VERSION 5.8 ;
BUSBITCHARS "[]" ;
DIVIDERCHAR "/" ;
UNITS
    DATABASE MICRONS 1000 ;
END UNITS

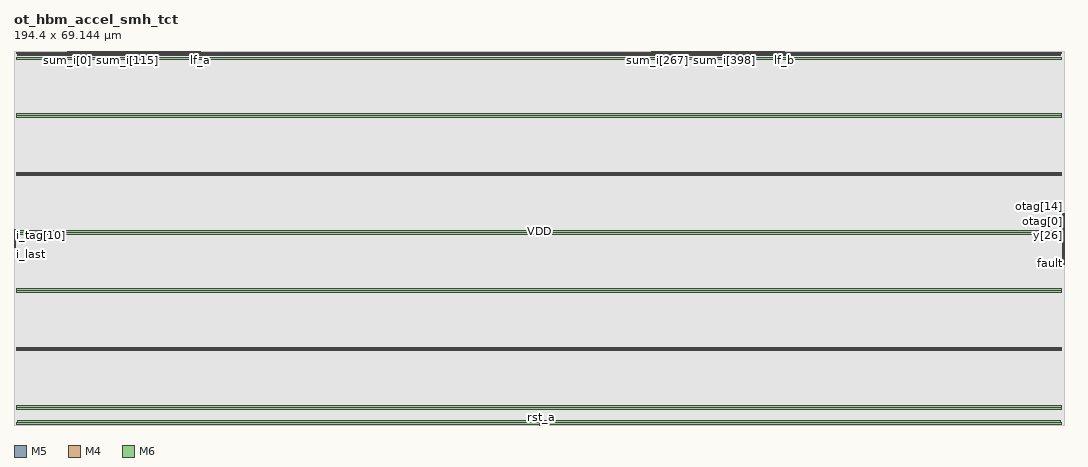
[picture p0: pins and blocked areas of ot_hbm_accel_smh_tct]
MACRO ot_hbm_accel_smh_tct
  FOREIGN ot_hbm_accel_smh_tct 0 0 ;
  CLASS BLOCK ;
  SIZE 194.4 BY 69.144 ;
  PIN clk
    DIRECTION INPUT ;
    USE SIGNAL ;
    PORT
      LAYER M5 ;
        RECT  97.2 0 97.224 0.192 ;
    END
  END clk
  PIN fault
    DIRECTION OUTPUT ;
    USE SIGNAL ;
    PORT
      LAYER M4 ;
        RECT  194.208 29.952 194.4 29.976 ;
    END
  END fault
  PIN i_last
    DIRECTION INPUT ;
    USE SIGNAL ;
    PORT
      LAYER M4 ;
        RECT  0 33.024 0.192 33.048 ;
    END
  END i_last
  PIN i_tag[0]
    DIRECTION INPUT ;
    USE SIGNAL ;
    PORT
      LAYER M4 ;
        RECT  0 33.216 0.192 33.24 ;
    END
  END i_tag[0]
  PIN i_tag[10]
    DIRECTION INPUT ;
    USE SIGNAL ;
    PORT
      LAYER M4 ;
        RECT  0 35.136 0.192 35.16 ;
    END
  END i_tag[10]
  PIN i_tag[11]
    DIRECTION INPUT ;
    USE SIGNAL ;
    PORT
      LAYER M4 ;
        RECT  0 35.328 0.192 35.352 ;
    END
  END i_tag[11]
  PIN i_tag[12]
    DIRECTION INPUT ;
    USE SIGNAL ;
    PORT
      LAYER M4 ;
        RECT  0 35.52 0.192 35.544 ;
    END
  END i_tag[12]
  PIN i_tag[13]
    DIRECTION INPUT ;
    USE SIGNAL ;
    PORT
      LAYER M4 ;
        RECT  0 35.712 0.192 35.736 ;
    END
  END i_tag[13]
  PIN i_tag[14]
    DIRECTION INPUT ;
    USE SIGNAL ;
    PORT
      LAYER M4 ;
        RECT  0 35.904 0.192 35.928 ;
    END
  END i_tag[14]
  PIN i_tag[15]
    DIRECTION INPUT ;
    USE SIGNAL ;
    PORT
      LAYER M4 ;
        RECT  0 36.096 0.192 36.12 ;
    END
  END i_tag[15]
  PIN i_tag[1]
    DIRECTION INPUT ;
    USE SIGNAL ;
    PORT
      LAYER M4 ;
        RECT  0 33.408 0.192 33.432 ;
    END
  END i_tag[1]
  PIN i_tag[2]
    DIRECTION INPUT ;
    USE SIGNAL ;
    PORT
      LAYER M4 ;
        RECT  0 33.6 0.192 33.624 ;
    END
  END i_tag[2]
  PIN i_tag[3]
    DIRECTION INPUT ;
    USE SIGNAL ;
    PORT
      LAYER M4 ;
        RECT  0 33.792 0.192 33.816 ;
    END
  END i_tag[3]
  PIN i_tag[4]
    DIRECTION INPUT ;
    USE SIGNAL ;
    PORT
      LAYER M4 ;
        RECT  0 33.984 0.192 34.008 ;
    END
  END i_tag[4]
  PIN i_tag[5]
    DIRECTION INPUT ;
    USE SIGNAL ;
    PORT
      LAYER M4 ;
        RECT  0 34.176 0.192 34.2 ;
    END
  END i_tag[5]
  PIN i_tag[6]
    DIRECTION INPUT ;
    USE SIGNAL ;
    PORT
      LAYER M4 ;
        RECT  0 34.368 0.192 34.392 ;
    END
  END i_tag[6]
  PIN i_tag[7]
    DIRECTION INPUT ;
    USE SIGNAL ;
    PORT
      LAYER M4 ;
        RECT  0 34.56 0.192 34.584 ;
    END
  END i_tag[7]
  PIN i_tag[8]
    DIRECTION INPUT ;
    USE SIGNAL ;
    PORT
      LAYER M4 ;
        RECT  0 34.752 0.192 34.776 ;
    END
  END i_tag[8]
  PIN i_tag[9]
    DIRECTION INPUT ;
    USE SIGNAL ;
    PORT
      LAYER M4 ;
        RECT  0 34.944 0.192 34.968 ;
    END
  END i_tag[9]
  PIN i_v
    DIRECTION INPUT ;
    USE SIGNAL ;
    PORT
      LAYER M4 ;
        RECT  0 32.832 0.192 32.856 ;
    END
  END i_v
  PIN lf_a
    DIRECTION INPUT ;
    USE SIGNAL ;
    PORT
      LAYER M5 ;
        RECT  34.56 68.952 34.584 69.144 ;
    END
  END lf_a
  PIN lf_b
    DIRECTION INPUT ;
    USE SIGNAL ;
    PORT
      LAYER M5 ;
        RECT  142.56 68.952 142.584 69.144 ;
    END
  END lf_b
  PIN otag[0]
    DIRECTION OUTPUT ;
    USE SIGNAL ;
    PORT
      LAYER M4 ;
        RECT  194.208 36.288 194.4 36.312 ;
    END
  END otag[0]
  PIN otag[10]
    DIRECTION OUTPUT ;
    USE SIGNAL ;
    PORT
      LAYER M4 ;
        RECT  194.208 38.208 194.4 38.232 ;
    END
  END otag[10]
  PIN otag[11]
    DIRECTION OUTPUT ;
    USE SIGNAL ;
    PORT
      LAYER M4 ;
        RECT  194.208 38.4 194.4 38.424 ;
    END
  END otag[11]
  PIN otag[12]
    DIRECTION OUTPUT ;
    USE SIGNAL ;
    PORT
      LAYER M4 ;
        RECT  194.208 38.592 194.4 38.616 ;
    END
  END otag[12]
  PIN otag[13]
    DIRECTION OUTPUT ;
    USE SIGNAL ;
    PORT
      LAYER M4 ;
        RECT  194.208 38.784 194.4 38.808 ;
    END
  END otag[13]
  PIN otag[14]
    DIRECTION OUTPUT ;
    USE SIGNAL ;
    PORT
      LAYER M4 ;
        RECT  194.208 38.976 194.4 39 ;
    END
  END otag[14]
  PIN otag[15]
    DIRECTION OUTPUT ;
    USE SIGNAL ;
    PORT
      LAYER M4 ;
        RECT  194.208 39.168 194.4 39.192 ;
    END
  END otag[15]
  PIN otag[1]
    DIRECTION OUTPUT ;
    USE SIGNAL ;
    PORT
      LAYER M4 ;
        RECT  194.208 36.48 194.4 36.504 ;
    END
  END otag[1]
  PIN otag[2]
    DIRECTION OUTPUT ;
    USE SIGNAL ;
    PORT
      LAYER M4 ;
        RECT  194.208 36.672 194.4 36.696 ;
    END
  END otag[2]
  PIN otag[3]
    DIRECTION OUTPUT ;
    USE SIGNAL ;
    PORT
      LAYER M4 ;
        RECT  194.208 36.864 194.4 36.888 ;
    END
  END otag[3]
  PIN otag[4]
    DIRECTION OUTPUT ;
    USE SIGNAL ;
    PORT
      LAYER M4 ;
        RECT  194.208 37.056 194.4 37.08 ;
    END
  END otag[4]
  PIN otag[5]
    DIRECTION OUTPUT ;
    USE SIGNAL ;
    PORT
      LAYER M4 ;
        RECT  194.208 37.248 194.4 37.272 ;
    END
  END otag[5]
  PIN otag[6]
    DIRECTION OUTPUT ;
    USE SIGNAL ;
    PORT
      LAYER M4 ;
        RECT  194.208 37.44 194.4 37.464 ;
    END
  END otag[6]
  PIN otag[7]
    DIRECTION OUTPUT ;
    USE SIGNAL ;
    PORT
      LAYER M4 ;
        RECT  194.208 37.632 194.4 37.656 ;
    END
  END otag[7]
  PIN otag[8]
    DIRECTION OUTPUT ;
    USE SIGNAL ;
    PORT
      LAYER M4 ;
        RECT  194.208 37.824 194.4 37.848 ;
    END
  END otag[8]
  PIN otag[9]
    DIRECTION OUTPUT ;
    USE SIGNAL ;
    PORT
      LAYER M4 ;
        RECT  194.208 38.016 194.4 38.04 ;
    END
  END otag[9]
  PIN ov
    DIRECTION OUTPUT ;
    USE SIGNAL ;
    PORT
      LAYER M4 ;
        RECT  194.208 29.76 194.4 29.784 ;
    END
  END ov
  PIN rst_a
    DIRECTION INPUT ;
    USE SIGNAL ;
    PORT
      LAYER M5 ;
        RECT  97.68 0 97.704 0.192 ;
    END
  END rst_a
  PIN sum_i[0]
    DIRECTION INPUT ;
    USE SIGNAL ;
    PORT
      LAYER M5 ;
        RECT  9.984 68.952 10.008 69.144 ;
    END
  END sum_i[0]
  PIN sum_i[100]
    DIRECTION INPUT ;
    USE SIGNAL ;
    PORT
      LAYER M5 ;
        RECT  19.584 68.952 19.608 69.144 ;
    END
  END sum_i[100]
  PIN sum_i[101]
    DIRECTION INPUT ;
    USE SIGNAL ;
    PORT
      LAYER M5 ;
        RECT  19.68 68.952 19.704 69.144 ;
    END
  END sum_i[101]
  PIN sum_i[102]
    DIRECTION INPUT ;
    USE SIGNAL ;
    PORT
      LAYER M5 ;
        RECT  19.776 68.952 19.8 69.144 ;
    END
  END sum_i[102]
  PIN sum_i[103]
    DIRECTION INPUT ;
    USE SIGNAL ;
    PORT
      LAYER M5 ;
        RECT  19.872 68.952 19.896 69.144 ;
    END
  END sum_i[103]
  PIN sum_i[104]
    DIRECTION INPUT ;
    USE SIGNAL ;
    PORT
      LAYER M5 ;
        RECT  19.968 68.952 19.992 69.144 ;
    END
  END sum_i[104]
  PIN sum_i[105]
    DIRECTION INPUT ;
    USE SIGNAL ;
    PORT
      LAYER M5 ;
        RECT  20.064 68.952 20.088 69.144 ;
    END
  END sum_i[105]
  PIN sum_i[106]
    DIRECTION INPUT ;
    USE SIGNAL ;
    PORT
      LAYER M5 ;
        RECT  20.16 68.952 20.184 69.144 ;
    END
  END sum_i[106]
  PIN sum_i[107]
    DIRECTION INPUT ;
    USE SIGNAL ;
    PORT
      LAYER M5 ;
        RECT  20.256 68.952 20.28 69.144 ;
    END
  END sum_i[107]
  PIN sum_i[108]
    DIRECTION INPUT ;
    USE SIGNAL ;
    PORT
      LAYER M5 ;
        RECT  20.352 68.952 20.376 69.144 ;
    END
  END sum_i[108]
  PIN sum_i[109]
    DIRECTION INPUT ;
    USE SIGNAL ;
    PORT
      LAYER M5 ;
        RECT  20.448 68.952 20.472 69.144 ;
    END
  END sum_i[109]
  PIN sum_i[10]
    DIRECTION INPUT ;
    USE SIGNAL ;
    PORT
      LAYER M5 ;
        RECT  10.944 68.952 10.968 69.144 ;
    END
  END sum_i[10]
  PIN sum_i[110]
    DIRECTION INPUT ;
    USE SIGNAL ;
    PORT
      LAYER M5 ;
        RECT  20.544 68.952 20.568 69.144 ;
    END
  END sum_i[110]
  PIN sum_i[111]
    DIRECTION INPUT ;
    USE SIGNAL ;
    PORT
      LAYER M5 ;
        RECT  20.64 68.952 20.664 69.144 ;
    END
  END sum_i[111]
  PIN sum_i[112]
    DIRECTION INPUT ;
    USE SIGNAL ;
    PORT
      LAYER M5 ;
        RECT  20.736 68.952 20.76 69.144 ;
    END
  END sum_i[112]
  PIN sum_i[113]
    DIRECTION INPUT ;
    USE SIGNAL ;
    PORT
      LAYER M5 ;
        RECT  20.832 68.952 20.856 69.144 ;
    END
  END sum_i[113]
  PIN sum_i[114]
    DIRECTION INPUT ;
    USE SIGNAL ;
    PORT
      LAYER M5 ;
        RECT  20.928 68.952 20.952 69.144 ;
    END
  END sum_i[114]
  PIN sum_i[115]
    DIRECTION INPUT ;
    USE SIGNAL ;
    PORT
      LAYER M5 ;
        RECT  21.024 68.952 21.048 69.144 ;
    END
  END sum_i[115]
  PIN sum_i[116]
    DIRECTION INPUT ;
    USE SIGNAL ;
    PORT
      LAYER M5 ;
        RECT  21.12 68.952 21.144 69.144 ;
    END
  END sum_i[116]
  PIN sum_i[117]
    DIRECTION INPUT ;
    USE SIGNAL ;
    PORT
      LAYER M5 ;
        RECT  21.216 68.952 21.24 69.144 ;
    END
  END sum_i[117]
  PIN sum_i[118]
    DIRECTION INPUT ;
    USE SIGNAL ;
    PORT
      LAYER M5 ;
        RECT  21.312 68.952 21.336 69.144 ;
    END
  END sum_i[118]
  PIN sum_i[119]
    DIRECTION INPUT ;
    USE SIGNAL ;
    PORT
      LAYER M5 ;
        RECT  21.408 68.952 21.432 69.144 ;
    END
  END sum_i[119]
  PIN sum_i[11]
    DIRECTION INPUT ;
    USE SIGNAL ;
    PORT
      LAYER M5 ;
        RECT  11.04 68.952 11.064 69.144 ;
    END
  END sum_i[11]
  PIN sum_i[120]
    DIRECTION INPUT ;
    USE SIGNAL ;
    PORT
      LAYER M5 ;
        RECT  21.504 68.952 21.528 69.144 ;
    END
  END sum_i[120]
  PIN sum_i[121]
    DIRECTION INPUT ;
    USE SIGNAL ;
    PORT
      LAYER M5 ;
        RECT  21.6 68.952 21.624 69.144 ;
    END
  END sum_i[121]
  PIN sum_i[122]
    DIRECTION INPUT ;
    USE SIGNAL ;
    PORT
      LAYER M5 ;
        RECT  21.696 68.952 21.72 69.144 ;
    END
  END sum_i[122]
  PIN sum_i[123]
    DIRECTION INPUT ;
    USE SIGNAL ;
    PORT
      LAYER M5 ;
        RECT  21.792 68.952 21.816 69.144 ;
    END
  END sum_i[123]
  PIN sum_i[124]
    DIRECTION INPUT ;
    USE SIGNAL ;
    PORT
      LAYER M5 ;
        RECT  21.888 68.952 21.912 69.144 ;
    END
  END sum_i[124]
  PIN sum_i[125]
    DIRECTION INPUT ;
    USE SIGNAL ;
    PORT
      LAYER M5 ;
        RECT  21.984 68.952 22.008 69.144 ;
    END
  END sum_i[125]
  PIN sum_i[126]
    DIRECTION INPUT ;
    USE SIGNAL ;
    PORT
      LAYER M5 ;
        RECT  22.08 68.952 22.104 69.144 ;
    END
  END sum_i[126]
  PIN sum_i[127]
    DIRECTION INPUT ;
    USE SIGNAL ;
    PORT
      LAYER M5 ;
        RECT  22.176 68.952 22.2 69.144 ;
    END
  END sum_i[127]
  PIN sum_i[128]
    DIRECTION INPUT ;
    USE SIGNAL ;
    PORT
      LAYER M5 ;
        RECT  22.272 68.952 22.296 69.144 ;
    END
  END sum_i[128]
  PIN sum_i[129]
    DIRECTION INPUT ;
    USE SIGNAL ;
    PORT
      LAYER M5 ;
        RECT  22.368 68.952 22.392 69.144 ;
    END
  END sum_i[129]
  PIN sum_i[12]
    DIRECTION INPUT ;
    USE SIGNAL ;
    PORT
      LAYER M5 ;
        RECT  11.136 68.952 11.16 69.144 ;
    END
  END sum_i[12]
  PIN sum_i[130]
    DIRECTION INPUT ;
    USE SIGNAL ;
    PORT
      LAYER M5 ;
        RECT  22.464 68.952 22.488 69.144 ;
    END
  END sum_i[130]
  PIN sum_i[131]
    DIRECTION INPUT ;
    USE SIGNAL ;
    PORT
      LAYER M5 ;
        RECT  22.56 68.952 22.584 69.144 ;
    END
  END sum_i[131]
  PIN sum_i[132]
    DIRECTION INPUT ;
    USE SIGNAL ;
    PORT
      LAYER M5 ;
        RECT  22.656 68.952 22.68 69.144 ;
    END
  END sum_i[132]
  PIN sum_i[133]
    DIRECTION INPUT ;
    USE SIGNAL ;
    PORT
      LAYER M5 ;
        RECT  22.752 68.952 22.776 69.144 ;
    END
  END sum_i[133]
  PIN sum_i[134]
    DIRECTION INPUT ;
    USE SIGNAL ;
    PORT
      LAYER M5 ;
        RECT  22.848 68.952 22.872 69.144 ;
    END
  END sum_i[134]
  PIN sum_i[135]
    DIRECTION INPUT ;
    USE SIGNAL ;
    PORT
      LAYER M5 ;
        RECT  22.944 68.952 22.968 69.144 ;
    END
  END sum_i[135]
  PIN sum_i[136]
    DIRECTION INPUT ;
    USE SIGNAL ;
    PORT
      LAYER M5 ;
        RECT  23.04 68.952 23.064 69.144 ;
    END
  END sum_i[136]
  PIN sum_i[137]
    DIRECTION INPUT ;
    USE SIGNAL ;
    PORT
      LAYER M5 ;
        RECT  23.136 68.952 23.16 69.144 ;
    END
  END sum_i[137]
  PIN sum_i[138]
    DIRECTION INPUT ;
    USE SIGNAL ;
    PORT
      LAYER M5 ;
        RECT  23.232 68.952 23.256 69.144 ;
    END
  END sum_i[138]
  PIN sum_i[139]
    DIRECTION INPUT ;
    USE SIGNAL ;
    PORT
      LAYER M5 ;
        RECT  23.328 68.952 23.352 69.144 ;
    END
  END sum_i[139]
  PIN sum_i[13]
    DIRECTION INPUT ;
    USE SIGNAL ;
    PORT
      LAYER M5 ;
        RECT  11.232 68.952 11.256 69.144 ;
    END
  END sum_i[13]
  PIN sum_i[140]
    DIRECTION INPUT ;
    USE SIGNAL ;
    PORT
      LAYER M5 ;
        RECT  23.424 68.952 23.448 69.144 ;
    END
  END sum_i[140]
  PIN sum_i[141]
    DIRECTION INPUT ;
    USE SIGNAL ;
    PORT
      LAYER M5 ;
        RECT  23.52 68.952 23.544 69.144 ;
    END
  END sum_i[141]
  PIN sum_i[142]
    DIRECTION INPUT ;
    USE SIGNAL ;
    PORT
      LAYER M5 ;
        RECT  23.616 68.952 23.64 69.144 ;
    END
  END sum_i[142]
  PIN sum_i[143]
    DIRECTION INPUT ;
    USE SIGNAL ;
    PORT
      LAYER M5 ;
        RECT  23.712 68.952 23.736 69.144 ;
    END
  END sum_i[143]
  PIN sum_i[144]
    DIRECTION INPUT ;
    USE SIGNAL ;
    PORT
      LAYER M5 ;
        RECT  23.808 68.952 23.832 69.144 ;
    END
  END sum_i[144]
  PIN sum_i[145]
    DIRECTION INPUT ;
    USE SIGNAL ;
    PORT
      LAYER M5 ;
        RECT  23.904 68.952 23.928 69.144 ;
    END
  END sum_i[145]
  PIN sum_i[146]
    DIRECTION INPUT ;
    USE SIGNAL ;
    PORT
      LAYER M5 ;
        RECT  24 68.952 24.024 69.144 ;
    END
  END sum_i[146]
  PIN sum_i[147]
    DIRECTION INPUT ;
    USE SIGNAL ;
    PORT
      LAYER M5 ;
        RECT  24.096 68.952 24.12 69.144 ;
    END
  END sum_i[147]
  PIN sum_i[148]
    DIRECTION INPUT ;
    USE SIGNAL ;
    PORT
      LAYER M5 ;
        RECT  24.192 68.952 24.216 69.144 ;
    END
  END sum_i[148]
  PIN sum_i[149]
    DIRECTION INPUT ;
    USE SIGNAL ;
    PORT
      LAYER M5 ;
        RECT  24.288 68.952 24.312 69.144 ;
    END
  END sum_i[149]
  PIN sum_i[14]
    DIRECTION INPUT ;
    USE SIGNAL ;
    PORT
      LAYER M5 ;
        RECT  11.328 68.952 11.352 69.144 ;
    END
  END sum_i[14]
  PIN sum_i[150]
    DIRECTION INPUT ;
    USE SIGNAL ;
    PORT
      LAYER M5 ;
        RECT  24.384 68.952 24.408 69.144 ;
    END
  END sum_i[150]
  PIN sum_i[151]
    DIRECTION INPUT ;
    USE SIGNAL ;
    PORT
      LAYER M5 ;
        RECT  24.48 68.952 24.504 69.144 ;
    END
  END sum_i[151]
  PIN sum_i[152]
    DIRECTION INPUT ;
    USE SIGNAL ;
    PORT
      LAYER M5 ;
        RECT  24.576 68.952 24.6 69.144 ;
    END
  END sum_i[152]
  PIN sum_i[153]
    DIRECTION INPUT ;
    USE SIGNAL ;
    PORT
      LAYER M5 ;
        RECT  24.672 68.952 24.696 69.144 ;
    END
  END sum_i[153]
  PIN sum_i[154]
    DIRECTION INPUT ;
    USE SIGNAL ;
    PORT
      LAYER M5 ;
        RECT  24.768 68.952 24.792 69.144 ;
    END
  END sum_i[154]
  PIN sum_i[155]
    DIRECTION INPUT ;
    USE SIGNAL ;
    PORT
      LAYER M5 ;
        RECT  24.864 68.952 24.888 69.144 ;
    END
  END sum_i[155]
  PIN sum_i[156]
    DIRECTION INPUT ;
    USE SIGNAL ;
    PORT
      LAYER M5 ;
        RECT  24.96 68.952 24.984 69.144 ;
    END
  END sum_i[156]
  PIN sum_i[157]
    DIRECTION INPUT ;
    USE SIGNAL ;
    PORT
      LAYER M5 ;
        RECT  25.056 68.952 25.08 69.144 ;
    END
  END sum_i[157]
  PIN sum_i[158]
    DIRECTION INPUT ;
    USE SIGNAL ;
    PORT
      LAYER M5 ;
        RECT  25.152 68.952 25.176 69.144 ;
    END
  END sum_i[158]
  PIN sum_i[159]
    DIRECTION INPUT ;
    USE SIGNAL ;
    PORT
      LAYER M5 ;
        RECT  25.248 68.952 25.272 69.144 ;
    END
  END sum_i[159]
  PIN sum_i[15]
    DIRECTION INPUT ;
    USE SIGNAL ;
    PORT
      LAYER M5 ;
        RECT  11.424 68.952 11.448 69.144 ;
    END
  END sum_i[15]
  PIN sum_i[160]
    DIRECTION INPUT ;
    USE SIGNAL ;
    PORT
      LAYER M5 ;
        RECT  25.344 68.952 25.368 69.144 ;
    END
  END sum_i[160]
  PIN sum_i[161]
    DIRECTION INPUT ;
    USE SIGNAL ;
    PORT
      LAYER M5 ;
        RECT  25.44 68.952 25.464 69.144 ;
    END
  END sum_i[161]
  PIN sum_i[162]
    DIRECTION INPUT ;
    USE SIGNAL ;
    PORT
      LAYER M5 ;
        RECT  25.536 68.952 25.56 69.144 ;
    END
  END sum_i[162]
  PIN sum_i[163]
    DIRECTION INPUT ;
    USE SIGNAL ;
    PORT
      LAYER M5 ;
        RECT  25.632 68.952 25.656 69.144 ;
    END
  END sum_i[163]
  PIN sum_i[164]
    DIRECTION INPUT ;
    USE SIGNAL ;
    PORT
      LAYER M5 ;
        RECT  25.728 68.952 25.752 69.144 ;
    END
  END sum_i[164]
  PIN sum_i[165]
    DIRECTION INPUT ;
    USE SIGNAL ;
    PORT
      LAYER M5 ;
        RECT  25.824 68.952 25.848 69.144 ;
    END
  END sum_i[165]
  PIN sum_i[166]
    DIRECTION INPUT ;
    USE SIGNAL ;
    PORT
      LAYER M5 ;
        RECT  25.92 68.952 25.944 69.144 ;
    END
  END sum_i[166]
  PIN sum_i[167]
    DIRECTION INPUT ;
    USE SIGNAL ;
    PORT
      LAYER M5 ;
        RECT  26.016 68.952 26.04 69.144 ;
    END
  END sum_i[167]
  PIN sum_i[168]
    DIRECTION INPUT ;
    USE SIGNAL ;
    PORT
      LAYER M5 ;
        RECT  26.112 68.952 26.136 69.144 ;
    END
  END sum_i[168]
  PIN sum_i[169]
    DIRECTION INPUT ;
    USE SIGNAL ;
    PORT
      LAYER M5 ;
        RECT  26.208 68.952 26.232 69.144 ;
    END
  END sum_i[169]
  PIN sum_i[16]
    DIRECTION INPUT ;
    USE SIGNAL ;
    PORT
      LAYER M5 ;
        RECT  11.52 68.952 11.544 69.144 ;
    END
  END sum_i[16]
  PIN sum_i[170]
    DIRECTION INPUT ;
    USE SIGNAL ;
    PORT
      LAYER M5 ;
        RECT  26.304 68.952 26.328 69.144 ;
    END
  END sum_i[170]
  PIN sum_i[171]
    DIRECTION INPUT ;
    USE SIGNAL ;
    PORT
      LAYER M5 ;
        RECT  26.4 68.952 26.424 69.144 ;
    END
  END sum_i[171]
  PIN sum_i[172]
    DIRECTION INPUT ;
    USE SIGNAL ;
    PORT
      LAYER M5 ;
        RECT  26.496 68.952 26.52 69.144 ;
    END
  END sum_i[172]
  PIN sum_i[173]
    DIRECTION INPUT ;
    USE SIGNAL ;
    PORT
      LAYER M5 ;
        RECT  26.592 68.952 26.616 69.144 ;
    END
  END sum_i[173]
  PIN sum_i[174]
    DIRECTION INPUT ;
    USE SIGNAL ;
    PORT
      LAYER M5 ;
        RECT  26.688 68.952 26.712 69.144 ;
    END
  END sum_i[174]
  PIN sum_i[175]
    DIRECTION INPUT ;
    USE SIGNAL ;
    PORT
      LAYER M5 ;
        RECT  26.784 68.952 26.808 69.144 ;
    END
  END sum_i[175]
  PIN sum_i[176]
    DIRECTION INPUT ;
    USE SIGNAL ;
    PORT
      LAYER M5 ;
        RECT  26.88 68.952 26.904 69.144 ;
    END
  END sum_i[176]
  PIN sum_i[177]
    DIRECTION INPUT ;
    USE SIGNAL ;
    PORT
      LAYER M5 ;
        RECT  26.976 68.952 27 69.144 ;
    END
  END sum_i[177]
  PIN sum_i[178]
    DIRECTION INPUT ;
    USE SIGNAL ;
    PORT
      LAYER M5 ;
        RECT  27.072 68.952 27.096 69.144 ;
    END
  END sum_i[178]
  PIN sum_i[179]
    DIRECTION INPUT ;
    USE SIGNAL ;
    PORT
      LAYER M5 ;
        RECT  27.168 68.952 27.192 69.144 ;
    END
  END sum_i[179]
  PIN sum_i[17]
    DIRECTION INPUT ;
    USE SIGNAL ;
    PORT
      LAYER M5 ;
        RECT  11.616 68.952 11.64 69.144 ;
    END
  END sum_i[17]
  PIN sum_i[180]
    DIRECTION INPUT ;
    USE SIGNAL ;
    PORT
      LAYER M5 ;
        RECT  27.264 68.952 27.288 69.144 ;
    END
  END sum_i[180]
  PIN sum_i[181]
    DIRECTION INPUT ;
    USE SIGNAL ;
    PORT
      LAYER M5 ;
        RECT  27.36 68.952 27.384 69.144 ;
    END
  END sum_i[181]
  PIN sum_i[182]
    DIRECTION INPUT ;
    USE SIGNAL ;
    PORT
      LAYER M5 ;
        RECT  27.456 68.952 27.48 69.144 ;
    END
  END sum_i[182]
  PIN sum_i[183]
    DIRECTION INPUT ;
    USE SIGNAL ;
    PORT
      LAYER M5 ;
        RECT  27.552 68.952 27.576 69.144 ;
    END
  END sum_i[183]
  PIN sum_i[184]
    DIRECTION INPUT ;
    USE SIGNAL ;
    PORT
      LAYER M5 ;
        RECT  27.648 68.952 27.672 69.144 ;
    END
  END sum_i[184]
  PIN sum_i[185]
    DIRECTION INPUT ;
    USE SIGNAL ;
    PORT
      LAYER M5 ;
        RECT  27.744 68.952 27.768 69.144 ;
    END
  END sum_i[185]
  PIN sum_i[186]
    DIRECTION INPUT ;
    USE SIGNAL ;
    PORT
      LAYER M5 ;
        RECT  27.84 68.952 27.864 69.144 ;
    END
  END sum_i[186]
  PIN sum_i[187]
    DIRECTION INPUT ;
    USE SIGNAL ;
    PORT
      LAYER M5 ;
        RECT  27.936 68.952 27.96 69.144 ;
    END
  END sum_i[187]
  PIN sum_i[188]
    DIRECTION INPUT ;
    USE SIGNAL ;
    PORT
      LAYER M5 ;
        RECT  28.032 68.952 28.056 69.144 ;
    END
  END sum_i[188]
  PIN sum_i[189]
    DIRECTION INPUT ;
    USE SIGNAL ;
    PORT
      LAYER M5 ;
        RECT  28.128 68.952 28.152 69.144 ;
    END
  END sum_i[189]
  PIN sum_i[18]
    DIRECTION INPUT ;
    USE SIGNAL ;
    PORT
      LAYER M5 ;
        RECT  11.712 68.952 11.736 69.144 ;
    END
  END sum_i[18]
  PIN sum_i[190]
    DIRECTION INPUT ;
    USE SIGNAL ;
    PORT
      LAYER M5 ;
        RECT  28.224 68.952 28.248 69.144 ;
    END
  END sum_i[190]
  PIN sum_i[191]
    DIRECTION INPUT ;
    USE SIGNAL ;
    PORT
      LAYER M5 ;
        RECT  28.32 68.952 28.344 69.144 ;
    END
  END sum_i[191]
  PIN sum_i[192]
    DIRECTION INPUT ;
    USE SIGNAL ;
    PORT
      LAYER M5 ;
        RECT  28.416 68.952 28.44 69.144 ;
    END
  END sum_i[192]
  PIN sum_i[193]
    DIRECTION INPUT ;
    USE SIGNAL ;
    PORT
      LAYER M5 ;
        RECT  28.512 68.952 28.536 69.144 ;
    END
  END sum_i[193]
  PIN sum_i[194]
    DIRECTION INPUT ;
    USE SIGNAL ;
    PORT
      LAYER M5 ;
        RECT  28.608 68.952 28.632 69.144 ;
    END
  END sum_i[194]
  PIN sum_i[195]
    DIRECTION INPUT ;
    USE SIGNAL ;
    PORT
      LAYER M5 ;
        RECT  28.704 68.952 28.728 69.144 ;
    END
  END sum_i[195]
  PIN sum_i[196]
    DIRECTION INPUT ;
    USE SIGNAL ;
    PORT
      LAYER M5 ;
        RECT  28.8 68.952 28.824 69.144 ;
    END
  END sum_i[196]
  PIN sum_i[197]
    DIRECTION INPUT ;
    USE SIGNAL ;
    PORT
      LAYER M5 ;
        RECT  28.896 68.952 28.92 69.144 ;
    END
  END sum_i[197]
  PIN sum_i[198]
    DIRECTION INPUT ;
    USE SIGNAL ;
    PORT
      LAYER M5 ;
        RECT  28.992 68.952 29.016 69.144 ;
    END
  END sum_i[198]
  PIN sum_i[199]
    DIRECTION INPUT ;
    USE SIGNAL ;
    PORT
      LAYER M5 ;
        RECT  29.088 68.952 29.112 69.144 ;
    END
  END sum_i[199]
  PIN sum_i[19]
    DIRECTION INPUT ;
    USE SIGNAL ;
    PORT
      LAYER M5 ;
        RECT  11.808 68.952 11.832 69.144 ;
    END
  END sum_i[19]
  PIN sum_i[1]
    DIRECTION INPUT ;
    USE SIGNAL ;
    PORT
      LAYER M5 ;
        RECT  10.08 68.952 10.104 69.144 ;
    END
  END sum_i[1]
  PIN sum_i[200]
    DIRECTION INPUT ;
    USE SIGNAL ;
    PORT
      LAYER M5 ;
        RECT  29.184 68.952 29.208 69.144 ;
    END
  END sum_i[200]
  PIN sum_i[201]
    DIRECTION INPUT ;
    USE SIGNAL ;
    PORT
      LAYER M5 ;
        RECT  29.28 68.952 29.304 69.144 ;
    END
  END sum_i[201]
  PIN sum_i[202]
    DIRECTION INPUT ;
    USE SIGNAL ;
    PORT
      LAYER M5 ;
        RECT  29.376 68.952 29.4 69.144 ;
    END
  END sum_i[202]
  PIN sum_i[203]
    DIRECTION INPUT ;
    USE SIGNAL ;
    PORT
      LAYER M5 ;
        RECT  29.472 68.952 29.496 69.144 ;
    END
  END sum_i[203]
  PIN sum_i[204]
    DIRECTION INPUT ;
    USE SIGNAL ;
    PORT
      LAYER M5 ;
        RECT  29.568 68.952 29.592 69.144 ;
    END
  END sum_i[204]
  PIN sum_i[205]
    DIRECTION INPUT ;
    USE SIGNAL ;
    PORT
      LAYER M5 ;
        RECT  29.664 68.952 29.688 69.144 ;
    END
  END sum_i[205]
  PIN sum_i[206]
    DIRECTION INPUT ;
    USE SIGNAL ;
    PORT
      LAYER M5 ;
        RECT  29.76 68.952 29.784 69.144 ;
    END
  END sum_i[206]
  PIN sum_i[207]
    DIRECTION INPUT ;
    USE SIGNAL ;
    PORT
      LAYER M5 ;
        RECT  29.856 68.952 29.88 69.144 ;
    END
  END sum_i[207]
  PIN sum_i[208]
    DIRECTION INPUT ;
    USE SIGNAL ;
    PORT
      LAYER M5 ;
        RECT  29.952 68.952 29.976 69.144 ;
    END
  END sum_i[208]
  PIN sum_i[209]
    DIRECTION INPUT ;
    USE SIGNAL ;
    PORT
      LAYER M5 ;
        RECT  30.048 68.952 30.072 69.144 ;
    END
  END sum_i[209]
  PIN sum_i[20]
    DIRECTION INPUT ;
    USE SIGNAL ;
    PORT
      LAYER M5 ;
        RECT  11.904 68.952 11.928 69.144 ;
    END
  END sum_i[20]
  PIN sum_i[210]
    DIRECTION INPUT ;
    USE SIGNAL ;
    PORT
      LAYER M5 ;
        RECT  30.144 68.952 30.168 69.144 ;
    END
  END sum_i[210]
  PIN sum_i[211]
    DIRECTION INPUT ;
    USE SIGNAL ;
    PORT
      LAYER M5 ;
        RECT  30.24 68.952 30.264 69.144 ;
    END
  END sum_i[211]
  PIN sum_i[212]
    DIRECTION INPUT ;
    USE SIGNAL ;
    PORT
      LAYER M5 ;
        RECT  30.336 68.952 30.36 69.144 ;
    END
  END sum_i[212]
  PIN sum_i[213]
    DIRECTION INPUT ;
    USE SIGNAL ;
    PORT
      LAYER M5 ;
        RECT  30.432 68.952 30.456 69.144 ;
    END
  END sum_i[213]
  PIN sum_i[214]
    DIRECTION INPUT ;
    USE SIGNAL ;
    PORT
      LAYER M5 ;
        RECT  30.528 68.952 30.552 69.144 ;
    END
  END sum_i[214]
  PIN sum_i[215]
    DIRECTION INPUT ;
    USE SIGNAL ;
    PORT
      LAYER M5 ;
        RECT  30.624 68.952 30.648 69.144 ;
    END
  END sum_i[215]
  PIN sum_i[216]
    DIRECTION INPUT ;
    USE SIGNAL ;
    PORT
      LAYER M5 ;
        RECT  30.72 68.952 30.744 69.144 ;
    END
  END sum_i[216]
  PIN sum_i[217]
    DIRECTION INPUT ;
    USE SIGNAL ;
    PORT
      LAYER M5 ;
        RECT  30.816 68.952 30.84 69.144 ;
    END
  END sum_i[217]
  PIN sum_i[218]
    DIRECTION INPUT ;
    USE SIGNAL ;
    PORT
      LAYER M5 ;
        RECT  30.912 68.952 30.936 69.144 ;
    END
  END sum_i[218]
  PIN sum_i[219]
    DIRECTION INPUT ;
    USE SIGNAL ;
    PORT
      LAYER M5 ;
        RECT  31.008 68.952 31.032 69.144 ;
    END
  END sum_i[219]
  PIN sum_i[21]
    DIRECTION INPUT ;
    USE SIGNAL ;
    PORT
      LAYER M5 ;
        RECT  12 68.952 12.024 69.144 ;
    END
  END sum_i[21]
  PIN sum_i[220]
    DIRECTION INPUT ;
    USE SIGNAL ;
    PORT
      LAYER M5 ;
        RECT  31.104 68.952 31.128 69.144 ;
    END
  END sum_i[220]
  PIN sum_i[221]
    DIRECTION INPUT ;
    USE SIGNAL ;
    PORT
      LAYER M5 ;
        RECT  31.2 68.952 31.224 69.144 ;
    END
  END sum_i[221]
  PIN sum_i[222]
    DIRECTION INPUT ;
    USE SIGNAL ;
    PORT
      LAYER M5 ;
        RECT  31.296 68.952 31.32 69.144 ;
    END
  END sum_i[222]
  PIN sum_i[223]
    DIRECTION INPUT ;
    USE SIGNAL ;
    PORT
      LAYER M5 ;
        RECT  31.392 68.952 31.416 69.144 ;
    END
  END sum_i[223]
  PIN sum_i[224]
    DIRECTION INPUT ;
    USE SIGNAL ;
    PORT
      LAYER M5 ;
        RECT  31.488 68.952 31.512 69.144 ;
    END
  END sum_i[224]
  PIN sum_i[225]
    DIRECTION INPUT ;
    USE SIGNAL ;
    PORT
      LAYER M5 ;
        RECT  31.584 68.952 31.608 69.144 ;
    END
  END sum_i[225]
  PIN sum_i[226]
    DIRECTION INPUT ;
    USE SIGNAL ;
    PORT
      LAYER M5 ;
        RECT  31.68 68.952 31.704 69.144 ;
    END
  END sum_i[226]
  PIN sum_i[227]
    DIRECTION INPUT ;
    USE SIGNAL ;
    PORT
      LAYER M5 ;
        RECT  31.776 68.952 31.8 69.144 ;
    END
  END sum_i[227]
  PIN sum_i[228]
    DIRECTION INPUT ;
    USE SIGNAL ;
    PORT
      LAYER M5 ;
        RECT  31.872 68.952 31.896 69.144 ;
    END
  END sum_i[228]
  PIN sum_i[229]
    DIRECTION INPUT ;
    USE SIGNAL ;
    PORT
      LAYER M5 ;
        RECT  31.968 68.952 31.992 69.144 ;
    END
  END sum_i[229]
  PIN sum_i[22]
    DIRECTION INPUT ;
    USE SIGNAL ;
    PORT
      LAYER M5 ;
        RECT  12.096 68.952 12.12 69.144 ;
    END
  END sum_i[22]
  PIN sum_i[230]
    DIRECTION INPUT ;
    USE SIGNAL ;
    PORT
      LAYER M5 ;
        RECT  32.064 68.952 32.088 69.144 ;
    END
  END sum_i[230]
  PIN sum_i[231]
    DIRECTION INPUT ;
    USE SIGNAL ;
    PORT
      LAYER M5 ;
        RECT  32.16 68.952 32.184 69.144 ;
    END
  END sum_i[231]
  PIN sum_i[232]
    DIRECTION INPUT ;
    USE SIGNAL ;
    PORT
      LAYER M5 ;
        RECT  32.256 68.952 32.28 69.144 ;
    END
  END sum_i[232]
  PIN sum_i[233]
    DIRECTION INPUT ;
    USE SIGNAL ;
    PORT
      LAYER M5 ;
        RECT  32.352 68.952 32.376 69.144 ;
    END
  END sum_i[233]
  PIN sum_i[234]
    DIRECTION INPUT ;
    USE SIGNAL ;
    PORT
      LAYER M5 ;
        RECT  32.448 68.952 32.472 69.144 ;
    END
  END sum_i[234]
  PIN sum_i[235]
    DIRECTION INPUT ;
    USE SIGNAL ;
    PORT
      LAYER M5 ;
        RECT  32.544 68.952 32.568 69.144 ;
    END
  END sum_i[235]
  PIN sum_i[236]
    DIRECTION INPUT ;
    USE SIGNAL ;
    PORT
      LAYER M5 ;
        RECT  32.64 68.952 32.664 69.144 ;
    END
  END sum_i[236]
  PIN sum_i[237]
    DIRECTION INPUT ;
    USE SIGNAL ;
    PORT
      LAYER M5 ;
        RECT  32.736 68.952 32.76 69.144 ;
    END
  END sum_i[237]
  PIN sum_i[238]
    DIRECTION INPUT ;
    USE SIGNAL ;
    PORT
      LAYER M5 ;
        RECT  32.832 68.952 32.856 69.144 ;
    END
  END sum_i[238]
  PIN sum_i[239]
    DIRECTION INPUT ;
    USE SIGNAL ;
    PORT
      LAYER M5 ;
        RECT  32.928 68.952 32.952 69.144 ;
    END
  END sum_i[239]
  PIN sum_i[23]
    DIRECTION INPUT ;
    USE SIGNAL ;
    PORT
      LAYER M5 ;
        RECT  12.192 68.952 12.216 69.144 ;
    END
  END sum_i[23]
  PIN sum_i[240]
    DIRECTION INPUT ;
    USE SIGNAL ;
    PORT
      LAYER M5 ;
        RECT  33.024 68.952 33.048 69.144 ;
    END
  END sum_i[240]
  PIN sum_i[241]
    DIRECTION INPUT ;
    USE SIGNAL ;
    PORT
      LAYER M5 ;
        RECT  33.12 68.952 33.144 69.144 ;
    END
  END sum_i[241]
  PIN sum_i[242]
    DIRECTION INPUT ;
    USE SIGNAL ;
    PORT
      LAYER M5 ;
        RECT  33.216 68.952 33.24 69.144 ;
    END
  END sum_i[242]
  PIN sum_i[243]
    DIRECTION INPUT ;
    USE SIGNAL ;
    PORT
      LAYER M5 ;
        RECT  33.312 68.952 33.336 69.144 ;
    END
  END sum_i[243]
  PIN sum_i[244]
    DIRECTION INPUT ;
    USE SIGNAL ;
    PORT
      LAYER M5 ;
        RECT  33.408 68.952 33.432 69.144 ;
    END
  END sum_i[244]
  PIN sum_i[245]
    DIRECTION INPUT ;
    USE SIGNAL ;
    PORT
      LAYER M5 ;
        RECT  33.504 68.952 33.528 69.144 ;
    END
  END sum_i[245]
  PIN sum_i[246]
    DIRECTION INPUT ;
    USE SIGNAL ;
    PORT
      LAYER M5 ;
        RECT  33.6 68.952 33.624 69.144 ;
    END
  END sum_i[246]
  PIN sum_i[247]
    DIRECTION INPUT ;
    USE SIGNAL ;
    PORT
      LAYER M5 ;
        RECT  33.696 68.952 33.72 69.144 ;
    END
  END sum_i[247]
  PIN sum_i[248]
    DIRECTION INPUT ;
    USE SIGNAL ;
    PORT
      LAYER M5 ;
        RECT  33.792 68.952 33.816 69.144 ;
    END
  END sum_i[248]
  PIN sum_i[249]
    DIRECTION INPUT ;
    USE SIGNAL ;
    PORT
      LAYER M5 ;
        RECT  33.888 68.952 33.912 69.144 ;
    END
  END sum_i[249]
  PIN sum_i[24]
    DIRECTION INPUT ;
    USE SIGNAL ;
    PORT
      LAYER M5 ;
        RECT  12.288 68.952 12.312 69.144 ;
    END
  END sum_i[24]
  PIN sum_i[250]
    DIRECTION INPUT ;
    USE SIGNAL ;
    PORT
      LAYER M5 ;
        RECT  33.984 68.952 34.008 69.144 ;
    END
  END sum_i[250]
  PIN sum_i[251]
    DIRECTION INPUT ;
    USE SIGNAL ;
    PORT
      LAYER M5 ;
        RECT  34.08 68.952 34.104 69.144 ;
    END
  END sum_i[251]
  PIN sum_i[252]
    DIRECTION INPUT ;
    USE SIGNAL ;
    PORT
      LAYER M5 ;
        RECT  34.176 68.952 34.2 69.144 ;
    END
  END sum_i[252]
  PIN sum_i[253]
    DIRECTION INPUT ;
    USE SIGNAL ;
    PORT
      LAYER M5 ;
        RECT  34.272 68.952 34.296 69.144 ;
    END
  END sum_i[253]
  PIN sum_i[254]
    DIRECTION INPUT ;
    USE SIGNAL ;
    PORT
      LAYER M5 ;
        RECT  34.368 68.952 34.392 69.144 ;
    END
  END sum_i[254]
  PIN sum_i[255]
    DIRECTION INPUT ;
    USE SIGNAL ;
    PORT
      LAYER M5 ;
        RECT  34.464 68.952 34.488 69.144 ;
    END
  END sum_i[255]
  PIN sum_i[256]
    DIRECTION INPUT ;
    USE SIGNAL ;
    PORT
      LAYER M5 ;
        RECT  117.984 68.952 118.008 69.144 ;
    END
  END sum_i[256]
  PIN sum_i[257]
    DIRECTION INPUT ;
    USE SIGNAL ;
    PORT
      LAYER M5 ;
        RECT  118.08 68.952 118.104 69.144 ;
    END
  END sum_i[257]
  PIN sum_i[258]
    DIRECTION INPUT ;
    USE SIGNAL ;
    PORT
      LAYER M5 ;
        RECT  118.176 68.952 118.2 69.144 ;
    END
  END sum_i[258]
  PIN sum_i[259]
    DIRECTION INPUT ;
    USE SIGNAL ;
    PORT
      LAYER M5 ;
        RECT  118.272 68.952 118.296 69.144 ;
    END
  END sum_i[259]
  PIN sum_i[25]
    DIRECTION INPUT ;
    USE SIGNAL ;
    PORT
      LAYER M5 ;
        RECT  12.384 68.952 12.408 69.144 ;
    END
  END sum_i[25]
  PIN sum_i[260]
    DIRECTION INPUT ;
    USE SIGNAL ;
    PORT
      LAYER M5 ;
        RECT  118.368 68.952 118.392 69.144 ;
    END
  END sum_i[260]
  PIN sum_i[261]
    DIRECTION INPUT ;
    USE SIGNAL ;
    PORT
      LAYER M5 ;
        RECT  118.464 68.952 118.488 69.144 ;
    END
  END sum_i[261]
  PIN sum_i[262]
    DIRECTION INPUT ;
    USE SIGNAL ;
    PORT
      LAYER M5 ;
        RECT  118.56 68.952 118.584 69.144 ;
    END
  END sum_i[262]
  PIN sum_i[263]
    DIRECTION INPUT ;
    USE SIGNAL ;
    PORT
      LAYER M5 ;
        RECT  118.656 68.952 118.68 69.144 ;
    END
  END sum_i[263]
  PIN sum_i[264]
    DIRECTION INPUT ;
    USE SIGNAL ;
    PORT
      LAYER M5 ;
        RECT  118.752 68.952 118.776 69.144 ;
    END
  END sum_i[264]
  PIN sum_i[265]
    DIRECTION INPUT ;
    USE SIGNAL ;
    PORT
      LAYER M5 ;
        RECT  118.848 68.952 118.872 69.144 ;
    END
  END sum_i[265]
  PIN sum_i[266]
    DIRECTION INPUT ;
    USE SIGNAL ;
    PORT
      LAYER M5 ;
        RECT  118.944 68.952 118.968 69.144 ;
    END
  END sum_i[266]
  PIN sum_i[267]
    DIRECTION INPUT ;
    USE SIGNAL ;
    PORT
      LAYER M5 ;
        RECT  119.04 68.952 119.064 69.144 ;
    END
  END sum_i[267]
  PIN sum_i[268]
    DIRECTION INPUT ;
    USE SIGNAL ;
    PORT
      LAYER M5 ;
        RECT  119.136 68.952 119.16 69.144 ;
    END
  END sum_i[268]
  PIN sum_i[269]
    DIRECTION INPUT ;
    USE SIGNAL ;
    PORT
      LAYER M5 ;
        RECT  119.232 68.952 119.256 69.144 ;
    END
  END sum_i[269]
  PIN sum_i[26]
    DIRECTION INPUT ;
    USE SIGNAL ;
    PORT
      LAYER M5 ;
        RECT  12.48 68.952 12.504 69.144 ;
    END
  END sum_i[26]
  PIN sum_i[270]
    DIRECTION INPUT ;
    USE SIGNAL ;
    PORT
      LAYER M5 ;
        RECT  119.328 68.952 119.352 69.144 ;
    END
  END sum_i[270]
  PIN sum_i[271]
    DIRECTION INPUT ;
    USE SIGNAL ;
    PORT
      LAYER M5 ;
        RECT  119.424 68.952 119.448 69.144 ;
    END
  END sum_i[271]
  PIN sum_i[272]
    DIRECTION INPUT ;
    USE SIGNAL ;
    PORT
      LAYER M5 ;
        RECT  119.52 68.952 119.544 69.144 ;
    END
  END sum_i[272]
  PIN sum_i[273]
    DIRECTION INPUT ;
    USE SIGNAL ;
    PORT
      LAYER M5 ;
        RECT  119.616 68.952 119.64 69.144 ;
    END
  END sum_i[273]
  PIN sum_i[274]
    DIRECTION INPUT ;
    USE SIGNAL ;
    PORT
      LAYER M5 ;
        RECT  119.712 68.952 119.736 69.144 ;
    END
  END sum_i[274]
  PIN sum_i[275]
    DIRECTION INPUT ;
    USE SIGNAL ;
    PORT
      LAYER M5 ;
        RECT  119.808 68.952 119.832 69.144 ;
    END
  END sum_i[275]
  PIN sum_i[276]
    DIRECTION INPUT ;
    USE SIGNAL ;
    PORT
      LAYER M5 ;
        RECT  119.904 68.952 119.928 69.144 ;
    END
  END sum_i[276]
  PIN sum_i[277]
    DIRECTION INPUT ;
    USE SIGNAL ;
    PORT
      LAYER M5 ;
        RECT  120 68.952 120.024 69.144 ;
    END
  END sum_i[277]
  PIN sum_i[278]
    DIRECTION INPUT ;
    USE SIGNAL ;
    PORT
      LAYER M5 ;
        RECT  120.096 68.952 120.12 69.144 ;
    END
  END sum_i[278]
  PIN sum_i[279]
    DIRECTION INPUT ;
    USE SIGNAL ;
    PORT
      LAYER M5 ;
        RECT  120.192 68.952 120.216 69.144 ;
    END
  END sum_i[279]
  PIN sum_i[27]
    DIRECTION INPUT ;
    USE SIGNAL ;
    PORT
      LAYER M5 ;
        RECT  12.576 68.952 12.6 69.144 ;
    END
  END sum_i[27]
  PIN sum_i[280]
    DIRECTION INPUT ;
    USE SIGNAL ;
    PORT
      LAYER M5 ;
        RECT  120.288 68.952 120.312 69.144 ;
    END
  END sum_i[280]
  PIN sum_i[281]
    DIRECTION INPUT ;
    USE SIGNAL ;
    PORT
      LAYER M5 ;
        RECT  120.384 68.952 120.408 69.144 ;
    END
  END sum_i[281]
  PIN sum_i[282]
    DIRECTION INPUT ;
    USE SIGNAL ;
    PORT
      LAYER M5 ;
        RECT  120.48 68.952 120.504 69.144 ;
    END
  END sum_i[282]
  PIN sum_i[283]
    DIRECTION INPUT ;
    USE SIGNAL ;
    PORT
      LAYER M5 ;
        RECT  120.576 68.952 120.6 69.144 ;
    END
  END sum_i[283]
  PIN sum_i[284]
    DIRECTION INPUT ;
    USE SIGNAL ;
    PORT
      LAYER M5 ;
        RECT  120.672 68.952 120.696 69.144 ;
    END
  END sum_i[284]
  PIN sum_i[285]
    DIRECTION INPUT ;
    USE SIGNAL ;
    PORT
      LAYER M5 ;
        RECT  120.768 68.952 120.792 69.144 ;
    END
  END sum_i[285]
  PIN sum_i[286]
    DIRECTION INPUT ;
    USE SIGNAL ;
    PORT
      LAYER M5 ;
        RECT  120.864 68.952 120.888 69.144 ;
    END
  END sum_i[286]
  PIN sum_i[287]
    DIRECTION INPUT ;
    USE SIGNAL ;
    PORT
      LAYER M5 ;
        RECT  120.96 68.952 120.984 69.144 ;
    END
  END sum_i[287]
  PIN sum_i[288]
    DIRECTION INPUT ;
    USE SIGNAL ;
    PORT
      LAYER M5 ;
        RECT  121.056 68.952 121.08 69.144 ;
    END
  END sum_i[288]
  PIN sum_i[289]
    DIRECTION INPUT ;
    USE SIGNAL ;
    PORT
      LAYER M5 ;
        RECT  121.152 68.952 121.176 69.144 ;
    END
  END sum_i[289]
  PIN sum_i[28]
    DIRECTION INPUT ;
    USE SIGNAL ;
    PORT
      LAYER M5 ;
        RECT  12.672 68.952 12.696 69.144 ;
    END
  END sum_i[28]
  PIN sum_i[290]
    DIRECTION INPUT ;
    USE SIGNAL ;
    PORT
      LAYER M5 ;
        RECT  121.248 68.952 121.272 69.144 ;
    END
  END sum_i[290]
  PIN sum_i[291]
    DIRECTION INPUT ;
    USE SIGNAL ;
    PORT
      LAYER M5 ;
        RECT  121.344 68.952 121.368 69.144 ;
    END
  END sum_i[291]
  PIN sum_i[292]
    DIRECTION INPUT ;
    USE SIGNAL ;
    PORT
      LAYER M5 ;
        RECT  121.44 68.952 121.464 69.144 ;
    END
  END sum_i[292]
  PIN sum_i[293]
    DIRECTION INPUT ;
    USE SIGNAL ;
    PORT
      LAYER M5 ;
        RECT  121.536 68.952 121.56 69.144 ;
    END
  END sum_i[293]
  PIN sum_i[294]
    DIRECTION INPUT ;
    USE SIGNAL ;
    PORT
      LAYER M5 ;
        RECT  121.632 68.952 121.656 69.144 ;
    END
  END sum_i[294]
  PIN sum_i[295]
    DIRECTION INPUT ;
    USE SIGNAL ;
    PORT
      LAYER M5 ;
        RECT  121.728 68.952 121.752 69.144 ;
    END
  END sum_i[295]
  PIN sum_i[296]
    DIRECTION INPUT ;
    USE SIGNAL ;
    PORT
      LAYER M5 ;
        RECT  121.824 68.952 121.848 69.144 ;
    END
  END sum_i[296]
  PIN sum_i[297]
    DIRECTION INPUT ;
    USE SIGNAL ;
    PORT
      LAYER M5 ;
        RECT  121.92 68.952 121.944 69.144 ;
    END
  END sum_i[297]
  PIN sum_i[298]
    DIRECTION INPUT ;
    USE SIGNAL ;
    PORT
      LAYER M5 ;
        RECT  122.016 68.952 122.04 69.144 ;
    END
  END sum_i[298]
  PIN sum_i[299]
    DIRECTION INPUT ;
    USE SIGNAL ;
    PORT
      LAYER M5 ;
        RECT  122.112 68.952 122.136 69.144 ;
    END
  END sum_i[299]
  PIN sum_i[29]
    DIRECTION INPUT ;
    USE SIGNAL ;
    PORT
      LAYER M5 ;
        RECT  12.768 68.952 12.792 69.144 ;
    END
  END sum_i[29]
  PIN sum_i[2]
    DIRECTION INPUT ;
    USE SIGNAL ;
    PORT
      LAYER M5 ;
        RECT  10.176 68.952 10.2 69.144 ;
    END
  END sum_i[2]
  PIN sum_i[300]
    DIRECTION INPUT ;
    USE SIGNAL ;
    PORT
      LAYER M5 ;
        RECT  122.208 68.952 122.232 69.144 ;
    END
  END sum_i[300]
  PIN sum_i[301]
    DIRECTION INPUT ;
    USE SIGNAL ;
    PORT
      LAYER M5 ;
        RECT  122.304 68.952 122.328 69.144 ;
    END
  END sum_i[301]
  PIN sum_i[302]
    DIRECTION INPUT ;
    USE SIGNAL ;
    PORT
      LAYER M5 ;
        RECT  122.4 68.952 122.424 69.144 ;
    END
  END sum_i[302]
  PIN sum_i[303]
    DIRECTION INPUT ;
    USE SIGNAL ;
    PORT
      LAYER M5 ;
        RECT  122.496 68.952 122.52 69.144 ;
    END
  END sum_i[303]
  PIN sum_i[304]
    DIRECTION INPUT ;
    USE SIGNAL ;
    PORT
      LAYER M5 ;
        RECT  122.592 68.952 122.616 69.144 ;
    END
  END sum_i[304]
  PIN sum_i[305]
    DIRECTION INPUT ;
    USE SIGNAL ;
    PORT
      LAYER M5 ;
        RECT  122.688 68.952 122.712 69.144 ;
    END
  END sum_i[305]
  PIN sum_i[306]
    DIRECTION INPUT ;
    USE SIGNAL ;
    PORT
      LAYER M5 ;
        RECT  122.784 68.952 122.808 69.144 ;
    END
  END sum_i[306]
  PIN sum_i[307]
    DIRECTION INPUT ;
    USE SIGNAL ;
    PORT
      LAYER M5 ;
        RECT  122.88 68.952 122.904 69.144 ;
    END
  END sum_i[307]
  PIN sum_i[308]
    DIRECTION INPUT ;
    USE SIGNAL ;
    PORT
      LAYER M5 ;
        RECT  122.976 68.952 123 69.144 ;
    END
  END sum_i[308]
  PIN sum_i[309]
    DIRECTION INPUT ;
    USE SIGNAL ;
    PORT
      LAYER M5 ;
        RECT  123.072 68.952 123.096 69.144 ;
    END
  END sum_i[309]
  PIN sum_i[30]
    DIRECTION INPUT ;
    USE SIGNAL ;
    PORT
      LAYER M5 ;
        RECT  12.864 68.952 12.888 69.144 ;
    END
  END sum_i[30]
  PIN sum_i[310]
    DIRECTION INPUT ;
    USE SIGNAL ;
    PORT
      LAYER M5 ;
        RECT  123.168 68.952 123.192 69.144 ;
    END
  END sum_i[310]
  PIN sum_i[311]
    DIRECTION INPUT ;
    USE SIGNAL ;
    PORT
      LAYER M5 ;
        RECT  123.264 68.952 123.288 69.144 ;
    END
  END sum_i[311]
  PIN sum_i[312]
    DIRECTION INPUT ;
    USE SIGNAL ;
    PORT
      LAYER M5 ;
        RECT  123.36 68.952 123.384 69.144 ;
    END
  END sum_i[312]
  PIN sum_i[313]
    DIRECTION INPUT ;
    USE SIGNAL ;
    PORT
      LAYER M5 ;
        RECT  123.456 68.952 123.48 69.144 ;
    END
  END sum_i[313]
  PIN sum_i[314]
    DIRECTION INPUT ;
    USE SIGNAL ;
    PORT
      LAYER M5 ;
        RECT  123.552 68.952 123.576 69.144 ;
    END
  END sum_i[314]
  PIN sum_i[315]
    DIRECTION INPUT ;
    USE SIGNAL ;
    PORT
      LAYER M5 ;
        RECT  123.648 68.952 123.672 69.144 ;
    END
  END sum_i[315]
  PIN sum_i[316]
    DIRECTION INPUT ;
    USE SIGNAL ;
    PORT
      LAYER M5 ;
        RECT  123.744 68.952 123.768 69.144 ;
    END
  END sum_i[316]
  PIN sum_i[317]
    DIRECTION INPUT ;
    USE SIGNAL ;
    PORT
      LAYER M5 ;
        RECT  123.84 68.952 123.864 69.144 ;
    END
  END sum_i[317]
  PIN sum_i[318]
    DIRECTION INPUT ;
    USE SIGNAL ;
    PORT
      LAYER M5 ;
        RECT  123.936 68.952 123.96 69.144 ;
    END
  END sum_i[318]
  PIN sum_i[319]
    DIRECTION INPUT ;
    USE SIGNAL ;
    PORT
      LAYER M5 ;
        RECT  124.032 68.952 124.056 69.144 ;
    END
  END sum_i[319]
  PIN sum_i[31]
    DIRECTION INPUT ;
    USE SIGNAL ;
    PORT
      LAYER M5 ;
        RECT  12.96 68.952 12.984 69.144 ;
    END
  END sum_i[31]
  PIN sum_i[320]
    DIRECTION INPUT ;
    USE SIGNAL ;
    PORT
      LAYER M5 ;
        RECT  124.128 68.952 124.152 69.144 ;
    END
  END sum_i[320]
  PIN sum_i[321]
    DIRECTION INPUT ;
    USE SIGNAL ;
    PORT
      LAYER M5 ;
        RECT  124.224 68.952 124.248 69.144 ;
    END
  END sum_i[321]
  PIN sum_i[322]
    DIRECTION INPUT ;
    USE SIGNAL ;
    PORT
      LAYER M5 ;
        RECT  124.32 68.952 124.344 69.144 ;
    END
  END sum_i[322]
  PIN sum_i[323]
    DIRECTION INPUT ;
    USE SIGNAL ;
    PORT
      LAYER M5 ;
        RECT  124.416 68.952 124.44 69.144 ;
    END
  END sum_i[323]
  PIN sum_i[324]
    DIRECTION INPUT ;
    USE SIGNAL ;
    PORT
      LAYER M5 ;
        RECT  124.512 68.952 124.536 69.144 ;
    END
  END sum_i[324]
  PIN sum_i[325]
    DIRECTION INPUT ;
    USE SIGNAL ;
    PORT
      LAYER M5 ;
        RECT  124.608 68.952 124.632 69.144 ;
    END
  END sum_i[325]
  PIN sum_i[326]
    DIRECTION INPUT ;
    USE SIGNAL ;
    PORT
      LAYER M5 ;
        RECT  124.704 68.952 124.728 69.144 ;
    END
  END sum_i[326]
  PIN sum_i[327]
    DIRECTION INPUT ;
    USE SIGNAL ;
    PORT
      LAYER M5 ;
        RECT  124.8 68.952 124.824 69.144 ;
    END
  END sum_i[327]
  PIN sum_i[328]
    DIRECTION INPUT ;
    USE SIGNAL ;
    PORT
      LAYER M5 ;
        RECT  124.896 68.952 124.92 69.144 ;
    END
  END sum_i[328]
  PIN sum_i[329]
    DIRECTION INPUT ;
    USE SIGNAL ;
    PORT
      LAYER M5 ;
        RECT  124.992 68.952 125.016 69.144 ;
    END
  END sum_i[329]
  PIN sum_i[32]
    DIRECTION INPUT ;
    USE SIGNAL ;
    PORT
      LAYER M5 ;
        RECT  13.056 68.952 13.08 69.144 ;
    END
  END sum_i[32]
  PIN sum_i[330]
    DIRECTION INPUT ;
    USE SIGNAL ;
    PORT
      LAYER M5 ;
        RECT  125.088 68.952 125.112 69.144 ;
    END
  END sum_i[330]
  PIN sum_i[331]
    DIRECTION INPUT ;
    USE SIGNAL ;
    PORT
      LAYER M5 ;
        RECT  125.184 68.952 125.208 69.144 ;
    END
  END sum_i[331]
  PIN sum_i[332]
    DIRECTION INPUT ;
    USE SIGNAL ;
    PORT
      LAYER M5 ;
        RECT  125.28 68.952 125.304 69.144 ;
    END
  END sum_i[332]
  PIN sum_i[333]
    DIRECTION INPUT ;
    USE SIGNAL ;
    PORT
      LAYER M5 ;
        RECT  125.376 68.952 125.4 69.144 ;
    END
  END sum_i[333]
  PIN sum_i[334]
    DIRECTION INPUT ;
    USE SIGNAL ;
    PORT
      LAYER M5 ;
        RECT  125.472 68.952 125.496 69.144 ;
    END
  END sum_i[334]
  PIN sum_i[335]
    DIRECTION INPUT ;
    USE SIGNAL ;
    PORT
      LAYER M5 ;
        RECT  125.568 68.952 125.592 69.144 ;
    END
  END sum_i[335]
  PIN sum_i[336]
    DIRECTION INPUT ;
    USE SIGNAL ;
    PORT
      LAYER M5 ;
        RECT  125.664 68.952 125.688 69.144 ;
    END
  END sum_i[336]
  PIN sum_i[337]
    DIRECTION INPUT ;
    USE SIGNAL ;
    PORT
      LAYER M5 ;
        RECT  125.76 68.952 125.784 69.144 ;
    END
  END sum_i[337]
  PIN sum_i[338]
    DIRECTION INPUT ;
    USE SIGNAL ;
    PORT
      LAYER M5 ;
        RECT  125.856 68.952 125.88 69.144 ;
    END
  END sum_i[338]
  PIN sum_i[339]
    DIRECTION INPUT ;
    USE SIGNAL ;
    PORT
      LAYER M5 ;
        RECT  125.952 68.952 125.976 69.144 ;
    END
  END sum_i[339]
  PIN sum_i[33]
    DIRECTION INPUT ;
    USE SIGNAL ;
    PORT
      LAYER M5 ;
        RECT  13.152 68.952 13.176 69.144 ;
    END
  END sum_i[33]
  PIN sum_i[340]
    DIRECTION INPUT ;
    USE SIGNAL ;
    PORT
      LAYER M5 ;
        RECT  126.048 68.952 126.072 69.144 ;
    END
  END sum_i[340]
  PIN sum_i[341]
    DIRECTION INPUT ;
    USE SIGNAL ;
    PORT
      LAYER M5 ;
        RECT  126.144 68.952 126.168 69.144 ;
    END
  END sum_i[341]
  PIN sum_i[342]
    DIRECTION INPUT ;
    USE SIGNAL ;
    PORT
      LAYER M5 ;
        RECT  126.24 68.952 126.264 69.144 ;
    END
  END sum_i[342]
  PIN sum_i[343]
    DIRECTION INPUT ;
    USE SIGNAL ;
    PORT
      LAYER M5 ;
        RECT  126.336 68.952 126.36 69.144 ;
    END
  END sum_i[343]
  PIN sum_i[344]
    DIRECTION INPUT ;
    USE SIGNAL ;
    PORT
      LAYER M5 ;
        RECT  126.432 68.952 126.456 69.144 ;
    END
  END sum_i[344]
  PIN sum_i[345]
    DIRECTION INPUT ;
    USE SIGNAL ;
    PORT
      LAYER M5 ;
        RECT  126.528 68.952 126.552 69.144 ;
    END
  END sum_i[345]
  PIN sum_i[346]
    DIRECTION INPUT ;
    USE SIGNAL ;
    PORT
      LAYER M5 ;
        RECT  126.624 68.952 126.648 69.144 ;
    END
  END sum_i[346]
  PIN sum_i[347]
    DIRECTION INPUT ;
    USE SIGNAL ;
    PORT
      LAYER M5 ;
        RECT  126.72 68.952 126.744 69.144 ;
    END
  END sum_i[347]
  PIN sum_i[348]
    DIRECTION INPUT ;
    USE SIGNAL ;
    PORT
      LAYER M5 ;
        RECT  126.816 68.952 126.84 69.144 ;
    END
  END sum_i[348]
  PIN sum_i[349]
    DIRECTION INPUT ;
    USE SIGNAL ;
    PORT
      LAYER M5 ;
        RECT  126.912 68.952 126.936 69.144 ;
    END
  END sum_i[349]
  PIN sum_i[34]
    DIRECTION INPUT ;
    USE SIGNAL ;
    PORT
      LAYER M5 ;
        RECT  13.248 68.952 13.272 69.144 ;
    END
  END sum_i[34]
  PIN sum_i[350]
    DIRECTION INPUT ;
    USE SIGNAL ;
    PORT
      LAYER M5 ;
        RECT  127.008 68.952 127.032 69.144 ;
    END
  END sum_i[350]
  PIN sum_i[351]
    DIRECTION INPUT ;
    USE SIGNAL ;
    PORT
      LAYER M5 ;
        RECT  127.104 68.952 127.128 69.144 ;
    END
  END sum_i[351]
  PIN sum_i[352]
    DIRECTION INPUT ;
    USE SIGNAL ;
    PORT
      LAYER M5 ;
        RECT  127.2 68.952 127.224 69.144 ;
    END
  END sum_i[352]
  PIN sum_i[353]
    DIRECTION INPUT ;
    USE SIGNAL ;
    PORT
      LAYER M5 ;
        RECT  127.296 68.952 127.32 69.144 ;
    END
  END sum_i[353]
  PIN sum_i[354]
    DIRECTION INPUT ;
    USE SIGNAL ;
    PORT
      LAYER M5 ;
        RECT  127.392 68.952 127.416 69.144 ;
    END
  END sum_i[354]
  PIN sum_i[355]
    DIRECTION INPUT ;
    USE SIGNAL ;
    PORT
      LAYER M5 ;
        RECT  127.488 68.952 127.512 69.144 ;
    END
  END sum_i[355]
  PIN sum_i[356]
    DIRECTION INPUT ;
    USE SIGNAL ;
    PORT
      LAYER M5 ;
        RECT  127.584 68.952 127.608 69.144 ;
    END
  END sum_i[356]
  PIN sum_i[357]
    DIRECTION INPUT ;
    USE SIGNAL ;
    PORT
      LAYER M5 ;
        RECT  127.68 68.952 127.704 69.144 ;
    END
  END sum_i[357]
  PIN sum_i[358]
    DIRECTION INPUT ;
    USE SIGNAL ;
    PORT
      LAYER M5 ;
        RECT  127.776 68.952 127.8 69.144 ;
    END
  END sum_i[358]
  PIN sum_i[359]
    DIRECTION INPUT ;
    USE SIGNAL ;
    PORT
      LAYER M5 ;
        RECT  127.872 68.952 127.896 69.144 ;
    END
  END sum_i[359]
  PIN sum_i[35]
    DIRECTION INPUT ;
    USE SIGNAL ;
    PORT
      LAYER M5 ;
        RECT  13.344 68.952 13.368 69.144 ;
    END
  END sum_i[35]
  PIN sum_i[360]
    DIRECTION INPUT ;
    USE SIGNAL ;
    PORT
      LAYER M5 ;
        RECT  127.968 68.952 127.992 69.144 ;
    END
  END sum_i[360]
  PIN sum_i[361]
    DIRECTION INPUT ;
    USE SIGNAL ;
    PORT
      LAYER M5 ;
        RECT  128.064 68.952 128.088 69.144 ;
    END
  END sum_i[361]
  PIN sum_i[362]
    DIRECTION INPUT ;
    USE SIGNAL ;
    PORT
      LAYER M5 ;
        RECT  128.16 68.952 128.184 69.144 ;
    END
  END sum_i[362]
  PIN sum_i[363]
    DIRECTION INPUT ;
    USE SIGNAL ;
    PORT
      LAYER M5 ;
        RECT  128.256 68.952 128.28 69.144 ;
    END
  END sum_i[363]
  PIN sum_i[364]
    DIRECTION INPUT ;
    USE SIGNAL ;
    PORT
      LAYER M5 ;
        RECT  128.352 68.952 128.376 69.144 ;
    END
  END sum_i[364]
  PIN sum_i[365]
    DIRECTION INPUT ;
    USE SIGNAL ;
    PORT
      LAYER M5 ;
        RECT  128.448 68.952 128.472 69.144 ;
    END
  END sum_i[365]
  PIN sum_i[366]
    DIRECTION INPUT ;
    USE SIGNAL ;
    PORT
      LAYER M5 ;
        RECT  128.544 68.952 128.568 69.144 ;
    END
  END sum_i[366]
  PIN sum_i[367]
    DIRECTION INPUT ;
    USE SIGNAL ;
    PORT
      LAYER M5 ;
        RECT  128.64 68.952 128.664 69.144 ;
    END
  END sum_i[367]
  PIN sum_i[368]
    DIRECTION INPUT ;
    USE SIGNAL ;
    PORT
      LAYER M5 ;
        RECT  128.736 68.952 128.76 69.144 ;
    END
  END sum_i[368]
  PIN sum_i[369]
    DIRECTION INPUT ;
    USE SIGNAL ;
    PORT
      LAYER M5 ;
        RECT  128.832 68.952 128.856 69.144 ;
    END
  END sum_i[369]
  PIN sum_i[36]
    DIRECTION INPUT ;
    USE SIGNAL ;
    PORT
      LAYER M5 ;
        RECT  13.44 68.952 13.464 69.144 ;
    END
  END sum_i[36]
  PIN sum_i[370]
    DIRECTION INPUT ;
    USE SIGNAL ;
    PORT
      LAYER M5 ;
        RECT  128.928 68.952 128.952 69.144 ;
    END
  END sum_i[370]
  PIN sum_i[371]
    DIRECTION INPUT ;
    USE SIGNAL ;
    PORT
      LAYER M5 ;
        RECT  129.024 68.952 129.048 69.144 ;
    END
  END sum_i[371]
  PIN sum_i[372]
    DIRECTION INPUT ;
    USE SIGNAL ;
    PORT
      LAYER M5 ;
        RECT  129.12 68.952 129.144 69.144 ;
    END
  END sum_i[372]
  PIN sum_i[373]
    DIRECTION INPUT ;
    USE SIGNAL ;
    PORT
      LAYER M5 ;
        RECT  129.216 68.952 129.24 69.144 ;
    END
  END sum_i[373]
  PIN sum_i[374]
    DIRECTION INPUT ;
    USE SIGNAL ;
    PORT
      LAYER M5 ;
        RECT  129.312 68.952 129.336 69.144 ;
    END
  END sum_i[374]
  PIN sum_i[375]
    DIRECTION INPUT ;
    USE SIGNAL ;
    PORT
      LAYER M5 ;
        RECT  129.408 68.952 129.432 69.144 ;
    END
  END sum_i[375]
  PIN sum_i[376]
    DIRECTION INPUT ;
    USE SIGNAL ;
    PORT
      LAYER M5 ;
        RECT  129.504 68.952 129.528 69.144 ;
    END
  END sum_i[376]
  PIN sum_i[377]
    DIRECTION INPUT ;
    USE SIGNAL ;
    PORT
      LAYER M5 ;
        RECT  129.6 68.952 129.624 69.144 ;
    END
  END sum_i[377]
  PIN sum_i[378]
    DIRECTION INPUT ;
    USE SIGNAL ;
    PORT
      LAYER M5 ;
        RECT  129.696 68.952 129.72 69.144 ;
    END
  END sum_i[378]
  PIN sum_i[379]
    DIRECTION INPUT ;
    USE SIGNAL ;
    PORT
      LAYER M5 ;
        RECT  129.792 68.952 129.816 69.144 ;
    END
  END sum_i[379]
  PIN sum_i[37]
    DIRECTION INPUT ;
    USE SIGNAL ;
    PORT
      LAYER M5 ;
        RECT  13.536 68.952 13.56 69.144 ;
    END
  END sum_i[37]
  PIN sum_i[380]
    DIRECTION INPUT ;
    USE SIGNAL ;
    PORT
      LAYER M5 ;
        RECT  129.888 68.952 129.912 69.144 ;
    END
  END sum_i[380]
  PIN sum_i[381]
    DIRECTION INPUT ;
    USE SIGNAL ;
    PORT
      LAYER M5 ;
        RECT  129.984 68.952 130.008 69.144 ;
    END
  END sum_i[381]
  PIN sum_i[382]
    DIRECTION INPUT ;
    USE SIGNAL ;
    PORT
      LAYER M5 ;
        RECT  130.08 68.952 130.104 69.144 ;
    END
  END sum_i[382]
  PIN sum_i[383]
    DIRECTION INPUT ;
    USE SIGNAL ;
    PORT
      LAYER M5 ;
        RECT  130.176 68.952 130.2 69.144 ;
    END
  END sum_i[383]
  PIN sum_i[384]
    DIRECTION INPUT ;
    USE SIGNAL ;
    PORT
      LAYER M5 ;
        RECT  130.272 68.952 130.296 69.144 ;
    END
  END sum_i[384]
  PIN sum_i[385]
    DIRECTION INPUT ;
    USE SIGNAL ;
    PORT
      LAYER M5 ;
        RECT  130.368 68.952 130.392 69.144 ;
    END
  END sum_i[385]
  PIN sum_i[386]
    DIRECTION INPUT ;
    USE SIGNAL ;
    PORT
      LAYER M5 ;
        RECT  130.464 68.952 130.488 69.144 ;
    END
  END sum_i[386]
  PIN sum_i[387]
    DIRECTION INPUT ;
    USE SIGNAL ;
    PORT
      LAYER M5 ;
        RECT  130.56 68.952 130.584 69.144 ;
    END
  END sum_i[387]
  PIN sum_i[388]
    DIRECTION INPUT ;
    USE SIGNAL ;
    PORT
      LAYER M5 ;
        RECT  130.656 68.952 130.68 69.144 ;
    END
  END sum_i[388]
  PIN sum_i[389]
    DIRECTION INPUT ;
    USE SIGNAL ;
    PORT
      LAYER M5 ;
        RECT  130.752 68.952 130.776 69.144 ;
    END
  END sum_i[389]
  PIN sum_i[38]
    DIRECTION INPUT ;
    USE SIGNAL ;
    PORT
      LAYER M5 ;
        RECT  13.632 68.952 13.656 69.144 ;
    END
  END sum_i[38]
  PIN sum_i[390]
    DIRECTION INPUT ;
    USE SIGNAL ;
    PORT
      LAYER M5 ;
        RECT  130.848 68.952 130.872 69.144 ;
    END
  END sum_i[390]
  PIN sum_i[391]
    DIRECTION INPUT ;
    USE SIGNAL ;
    PORT
      LAYER M5 ;
        RECT  130.944 68.952 130.968 69.144 ;
    END
  END sum_i[391]
  PIN sum_i[392]
    DIRECTION INPUT ;
    USE SIGNAL ;
    PORT
      LAYER M5 ;
        RECT  131.04 68.952 131.064 69.144 ;
    END
  END sum_i[392]
  PIN sum_i[393]
    DIRECTION INPUT ;
    USE SIGNAL ;
    PORT
      LAYER M5 ;
        RECT  131.136 68.952 131.16 69.144 ;
    END
  END sum_i[393]
  PIN sum_i[394]
    DIRECTION INPUT ;
    USE SIGNAL ;
    PORT
      LAYER M5 ;
        RECT  131.232 68.952 131.256 69.144 ;
    END
  END sum_i[394]
  PIN sum_i[395]
    DIRECTION INPUT ;
    USE SIGNAL ;
    PORT
      LAYER M5 ;
        RECT  131.328 68.952 131.352 69.144 ;
    END
  END sum_i[395]
  PIN sum_i[396]
    DIRECTION INPUT ;
    USE SIGNAL ;
    PORT
      LAYER M5 ;
        RECT  131.424 68.952 131.448 69.144 ;
    END
  END sum_i[396]
  PIN sum_i[397]
    DIRECTION INPUT ;
    USE SIGNAL ;
    PORT
      LAYER M5 ;
        RECT  131.52 68.952 131.544 69.144 ;
    END
  END sum_i[397]
  PIN sum_i[398]
    DIRECTION INPUT ;
    USE SIGNAL ;
    PORT
      LAYER M5 ;
        RECT  131.616 68.952 131.64 69.144 ;
    END
  END sum_i[398]
  PIN sum_i[399]
    DIRECTION INPUT ;
    USE SIGNAL ;
    PORT
      LAYER M5 ;
        RECT  131.712 68.952 131.736 69.144 ;
    END
  END sum_i[399]
  PIN sum_i[39]
    DIRECTION INPUT ;
    USE SIGNAL ;
    PORT
      LAYER M5 ;
        RECT  13.728 68.952 13.752 69.144 ;
    END
  END sum_i[39]
  PIN sum_i[3]
    DIRECTION INPUT ;
    USE SIGNAL ;
    PORT
      LAYER M5 ;
        RECT  10.272 68.952 10.296 69.144 ;
    END
  END sum_i[3]
  PIN sum_i[400]
    DIRECTION INPUT ;
    USE SIGNAL ;
    PORT
      LAYER M5 ;
        RECT  131.808 68.952 131.832 69.144 ;
    END
  END sum_i[400]
  PIN sum_i[401]
    DIRECTION INPUT ;
    USE SIGNAL ;
    PORT
      LAYER M5 ;
        RECT  131.904 68.952 131.928 69.144 ;
    END
  END sum_i[401]
  PIN sum_i[402]
    DIRECTION INPUT ;
    USE SIGNAL ;
    PORT
      LAYER M5 ;
        RECT  132 68.952 132.024 69.144 ;
    END
  END sum_i[402]
  PIN sum_i[403]
    DIRECTION INPUT ;
    USE SIGNAL ;
    PORT
      LAYER M5 ;
        RECT  132.096 68.952 132.12 69.144 ;
    END
  END sum_i[403]
  PIN sum_i[404]
    DIRECTION INPUT ;
    USE SIGNAL ;
    PORT
      LAYER M5 ;
        RECT  132.192 68.952 132.216 69.144 ;
    END
  END sum_i[404]
  PIN sum_i[405]
    DIRECTION INPUT ;
    USE SIGNAL ;
    PORT
      LAYER M5 ;
        RECT  132.288 68.952 132.312 69.144 ;
    END
  END sum_i[405]
  PIN sum_i[406]
    DIRECTION INPUT ;
    USE SIGNAL ;
    PORT
      LAYER M5 ;
        RECT  132.384 68.952 132.408 69.144 ;
    END
  END sum_i[406]
  PIN sum_i[407]
    DIRECTION INPUT ;
    USE SIGNAL ;
    PORT
      LAYER M5 ;
        RECT  132.48 68.952 132.504 69.144 ;
    END
  END sum_i[407]
  PIN sum_i[408]
    DIRECTION INPUT ;
    USE SIGNAL ;
    PORT
      LAYER M5 ;
        RECT  132.576 68.952 132.6 69.144 ;
    END
  END sum_i[408]
  PIN sum_i[409]
    DIRECTION INPUT ;
    USE SIGNAL ;
    PORT
      LAYER M5 ;
        RECT  132.672 68.952 132.696 69.144 ;
    END
  END sum_i[409]
  PIN sum_i[40]
    DIRECTION INPUT ;
    USE SIGNAL ;
    PORT
      LAYER M5 ;
        RECT  13.824 68.952 13.848 69.144 ;
    END
  END sum_i[40]
  PIN sum_i[410]
    DIRECTION INPUT ;
    USE SIGNAL ;
    PORT
      LAYER M5 ;
        RECT  132.768 68.952 132.792 69.144 ;
    END
  END sum_i[410]
  PIN sum_i[411]
    DIRECTION INPUT ;
    USE SIGNAL ;
    PORT
      LAYER M5 ;
        RECT  132.864 68.952 132.888 69.144 ;
    END
  END sum_i[411]
  PIN sum_i[412]
    DIRECTION INPUT ;
    USE SIGNAL ;
    PORT
      LAYER M5 ;
        RECT  132.96 68.952 132.984 69.144 ;
    END
  END sum_i[412]
  PIN sum_i[413]
    DIRECTION INPUT ;
    USE SIGNAL ;
    PORT
      LAYER M5 ;
        RECT  133.056 68.952 133.08 69.144 ;
    END
  END sum_i[413]
  PIN sum_i[414]
    DIRECTION INPUT ;
    USE SIGNAL ;
    PORT
      LAYER M5 ;
        RECT  133.152 68.952 133.176 69.144 ;
    END
  END sum_i[414]
  PIN sum_i[415]
    DIRECTION INPUT ;
    USE SIGNAL ;
    PORT
      LAYER M5 ;
        RECT  133.248 68.952 133.272 69.144 ;
    END
  END sum_i[415]
  PIN sum_i[416]
    DIRECTION INPUT ;
    USE SIGNAL ;
    PORT
      LAYER M5 ;
        RECT  133.344 68.952 133.368 69.144 ;
    END
  END sum_i[416]
  PIN sum_i[417]
    DIRECTION INPUT ;
    USE SIGNAL ;
    PORT
      LAYER M5 ;
        RECT  133.44 68.952 133.464 69.144 ;
    END
  END sum_i[417]
  PIN sum_i[418]
    DIRECTION INPUT ;
    USE SIGNAL ;
    PORT
      LAYER M5 ;
        RECT  133.536 68.952 133.56 69.144 ;
    END
  END sum_i[418]
  PIN sum_i[419]
    DIRECTION INPUT ;
    USE SIGNAL ;
    PORT
      LAYER M5 ;
        RECT  133.632 68.952 133.656 69.144 ;
    END
  END sum_i[419]
  PIN sum_i[41]
    DIRECTION INPUT ;
    USE SIGNAL ;
    PORT
      LAYER M5 ;
        RECT  13.92 68.952 13.944 69.144 ;
    END
  END sum_i[41]
  PIN sum_i[420]
    DIRECTION INPUT ;
    USE SIGNAL ;
    PORT
      LAYER M5 ;
        RECT  133.728 68.952 133.752 69.144 ;
    END
  END sum_i[420]
  PIN sum_i[421]
    DIRECTION INPUT ;
    USE SIGNAL ;
    PORT
      LAYER M5 ;
        RECT  133.824 68.952 133.848 69.144 ;
    END
  END sum_i[421]
  PIN sum_i[422]
    DIRECTION INPUT ;
    USE SIGNAL ;
    PORT
      LAYER M5 ;
        RECT  133.92 68.952 133.944 69.144 ;
    END
  END sum_i[422]
  PIN sum_i[423]
    DIRECTION INPUT ;
    USE SIGNAL ;
    PORT
      LAYER M5 ;
        RECT  134.016 68.952 134.04 69.144 ;
    END
  END sum_i[423]
  PIN sum_i[424]
    DIRECTION INPUT ;
    USE SIGNAL ;
    PORT
      LAYER M5 ;
        RECT  134.112 68.952 134.136 69.144 ;
    END
  END sum_i[424]
  PIN sum_i[425]
    DIRECTION INPUT ;
    USE SIGNAL ;
    PORT
      LAYER M5 ;
        RECT  134.208 68.952 134.232 69.144 ;
    END
  END sum_i[425]
  PIN sum_i[426]
    DIRECTION INPUT ;
    USE SIGNAL ;
    PORT
      LAYER M5 ;
        RECT  134.304 68.952 134.328 69.144 ;
    END
  END sum_i[426]
  PIN sum_i[427]
    DIRECTION INPUT ;
    USE SIGNAL ;
    PORT
      LAYER M5 ;
        RECT  134.4 68.952 134.424 69.144 ;
    END
  END sum_i[427]
  PIN sum_i[428]
    DIRECTION INPUT ;
    USE SIGNAL ;
    PORT
      LAYER M5 ;
        RECT  134.496 68.952 134.52 69.144 ;
    END
  END sum_i[428]
  PIN sum_i[429]
    DIRECTION INPUT ;
    USE SIGNAL ;
    PORT
      LAYER M5 ;
        RECT  134.592 68.952 134.616 69.144 ;
    END
  END sum_i[429]
  PIN sum_i[42]
    DIRECTION INPUT ;
    USE SIGNAL ;
    PORT
      LAYER M5 ;
        RECT  14.016 68.952 14.04 69.144 ;
    END
  END sum_i[42]
  PIN sum_i[430]
    DIRECTION INPUT ;
    USE SIGNAL ;
    PORT
      LAYER M5 ;
        RECT  134.688 68.952 134.712 69.144 ;
    END
  END sum_i[430]
  PIN sum_i[431]
    DIRECTION INPUT ;
    USE SIGNAL ;
    PORT
      LAYER M5 ;
        RECT  134.784 68.952 134.808 69.144 ;
    END
  END sum_i[431]
  PIN sum_i[432]
    DIRECTION INPUT ;
    USE SIGNAL ;
    PORT
      LAYER M5 ;
        RECT  134.88 68.952 134.904 69.144 ;
    END
  END sum_i[432]
  PIN sum_i[433]
    DIRECTION INPUT ;
    USE SIGNAL ;
    PORT
      LAYER M5 ;
        RECT  134.976 68.952 135 69.144 ;
    END
  END sum_i[433]
  PIN sum_i[434]
    DIRECTION INPUT ;
    USE SIGNAL ;
    PORT
      LAYER M5 ;
        RECT  135.072 68.952 135.096 69.144 ;
    END
  END sum_i[434]
  PIN sum_i[435]
    DIRECTION INPUT ;
    USE SIGNAL ;
    PORT
      LAYER M5 ;
        RECT  135.168 68.952 135.192 69.144 ;
    END
  END sum_i[435]
  PIN sum_i[436]
    DIRECTION INPUT ;
    USE SIGNAL ;
    PORT
      LAYER M5 ;
        RECT  135.264 68.952 135.288 69.144 ;
    END
  END sum_i[436]
  PIN sum_i[437]
    DIRECTION INPUT ;
    USE SIGNAL ;
    PORT
      LAYER M5 ;
        RECT  135.36 68.952 135.384 69.144 ;
    END
  END sum_i[437]
  PIN sum_i[438]
    DIRECTION INPUT ;
    USE SIGNAL ;
    PORT
      LAYER M5 ;
        RECT  135.456 68.952 135.48 69.144 ;
    END
  END sum_i[438]
  PIN sum_i[439]
    DIRECTION INPUT ;
    USE SIGNAL ;
    PORT
      LAYER M5 ;
        RECT  135.552 68.952 135.576 69.144 ;
    END
  END sum_i[439]
  PIN sum_i[43]
    DIRECTION INPUT ;
    USE SIGNAL ;
    PORT
      LAYER M5 ;
        RECT  14.112 68.952 14.136 69.144 ;
    END
  END sum_i[43]
  PIN sum_i[440]
    DIRECTION INPUT ;
    USE SIGNAL ;
    PORT
      LAYER M5 ;
        RECT  135.648 68.952 135.672 69.144 ;
    END
  END sum_i[440]
  PIN sum_i[441]
    DIRECTION INPUT ;
    USE SIGNAL ;
    PORT
      LAYER M5 ;
        RECT  135.744 68.952 135.768 69.144 ;
    END
  END sum_i[441]
  PIN sum_i[442]
    DIRECTION INPUT ;
    USE SIGNAL ;
    PORT
      LAYER M5 ;
        RECT  135.84 68.952 135.864 69.144 ;
    END
  END sum_i[442]
  PIN sum_i[443]
    DIRECTION INPUT ;
    USE SIGNAL ;
    PORT
      LAYER M5 ;
        RECT  135.936 68.952 135.96 69.144 ;
    END
  END sum_i[443]
  PIN sum_i[444]
    DIRECTION INPUT ;
    USE SIGNAL ;
    PORT
      LAYER M5 ;
        RECT  136.032 68.952 136.056 69.144 ;
    END
  END sum_i[444]
  PIN sum_i[445]
    DIRECTION INPUT ;
    USE SIGNAL ;
    PORT
      LAYER M5 ;
        RECT  136.128 68.952 136.152 69.144 ;
    END
  END sum_i[445]
  PIN sum_i[446]
    DIRECTION INPUT ;
    USE SIGNAL ;
    PORT
      LAYER M5 ;
        RECT  136.224 68.952 136.248 69.144 ;
    END
  END sum_i[446]
  PIN sum_i[447]
    DIRECTION INPUT ;
    USE SIGNAL ;
    PORT
      LAYER M5 ;
        RECT  136.32 68.952 136.344 69.144 ;
    END
  END sum_i[447]
  PIN sum_i[448]
    DIRECTION INPUT ;
    USE SIGNAL ;
    PORT
      LAYER M5 ;
        RECT  136.416 68.952 136.44 69.144 ;
    END
  END sum_i[448]
  PIN sum_i[449]
    DIRECTION INPUT ;
    USE SIGNAL ;
    PORT
      LAYER M5 ;
        RECT  136.512 68.952 136.536 69.144 ;
    END
  END sum_i[449]
  PIN sum_i[44]
    DIRECTION INPUT ;
    USE SIGNAL ;
    PORT
      LAYER M5 ;
        RECT  14.208 68.952 14.232 69.144 ;
    END
  END sum_i[44]
  PIN sum_i[450]
    DIRECTION INPUT ;
    USE SIGNAL ;
    PORT
      LAYER M5 ;
        RECT  136.608 68.952 136.632 69.144 ;
    END
  END sum_i[450]
  PIN sum_i[451]
    DIRECTION INPUT ;
    USE SIGNAL ;
    PORT
      LAYER M5 ;
        RECT  136.704 68.952 136.728 69.144 ;
    END
  END sum_i[451]
  PIN sum_i[452]
    DIRECTION INPUT ;
    USE SIGNAL ;
    PORT
      LAYER M5 ;
        RECT  136.8 68.952 136.824 69.144 ;
    END
  END sum_i[452]
  PIN sum_i[453]
    DIRECTION INPUT ;
    USE SIGNAL ;
    PORT
      LAYER M5 ;
        RECT  136.896 68.952 136.92 69.144 ;
    END
  END sum_i[453]
  PIN sum_i[454]
    DIRECTION INPUT ;
    USE SIGNAL ;
    PORT
      LAYER M5 ;
        RECT  136.992 68.952 137.016 69.144 ;
    END
  END sum_i[454]
  PIN sum_i[455]
    DIRECTION INPUT ;
    USE SIGNAL ;
    PORT
      LAYER M5 ;
        RECT  137.088 68.952 137.112 69.144 ;
    END
  END sum_i[455]
  PIN sum_i[456]
    DIRECTION INPUT ;
    USE SIGNAL ;
    PORT
      LAYER M5 ;
        RECT  137.184 68.952 137.208 69.144 ;
    END
  END sum_i[456]
  PIN sum_i[457]
    DIRECTION INPUT ;
    USE SIGNAL ;
    PORT
      LAYER M5 ;
        RECT  137.28 68.952 137.304 69.144 ;
    END
  END sum_i[457]
  PIN sum_i[458]
    DIRECTION INPUT ;
    USE SIGNAL ;
    PORT
      LAYER M5 ;
        RECT  137.376 68.952 137.4 69.144 ;
    END
  END sum_i[458]
  PIN sum_i[459]
    DIRECTION INPUT ;
    USE SIGNAL ;
    PORT
      LAYER M5 ;
        RECT  137.472 68.952 137.496 69.144 ;
    END
  END sum_i[459]
  PIN sum_i[45]
    DIRECTION INPUT ;
    USE SIGNAL ;
    PORT
      LAYER M5 ;
        RECT  14.304 68.952 14.328 69.144 ;
    END
  END sum_i[45]
  PIN sum_i[460]
    DIRECTION INPUT ;
    USE SIGNAL ;
    PORT
      LAYER M5 ;
        RECT  137.568 68.952 137.592 69.144 ;
    END
  END sum_i[460]
  PIN sum_i[461]
    DIRECTION INPUT ;
    USE SIGNAL ;
    PORT
      LAYER M5 ;
        RECT  137.664 68.952 137.688 69.144 ;
    END
  END sum_i[461]
  PIN sum_i[462]
    DIRECTION INPUT ;
    USE SIGNAL ;
    PORT
      LAYER M5 ;
        RECT  137.76 68.952 137.784 69.144 ;
    END
  END sum_i[462]
  PIN sum_i[463]
    DIRECTION INPUT ;
    USE SIGNAL ;
    PORT
      LAYER M5 ;
        RECT  137.856 68.952 137.88 69.144 ;
    END
  END sum_i[463]
  PIN sum_i[464]
    DIRECTION INPUT ;
    USE SIGNAL ;
    PORT
      LAYER M5 ;
        RECT  137.952 68.952 137.976 69.144 ;
    END
  END sum_i[464]
  PIN sum_i[465]
    DIRECTION INPUT ;
    USE SIGNAL ;
    PORT
      LAYER M5 ;
        RECT  138.048 68.952 138.072 69.144 ;
    END
  END sum_i[465]
  PIN sum_i[466]
    DIRECTION INPUT ;
    USE SIGNAL ;
    PORT
      LAYER M5 ;
        RECT  138.144 68.952 138.168 69.144 ;
    END
  END sum_i[466]
  PIN sum_i[467]
    DIRECTION INPUT ;
    USE SIGNAL ;
    PORT
      LAYER M5 ;
        RECT  138.24 68.952 138.264 69.144 ;
    END
  END sum_i[467]
  PIN sum_i[468]
    DIRECTION INPUT ;
    USE SIGNAL ;
    PORT
      LAYER M5 ;
        RECT  138.336 68.952 138.36 69.144 ;
    END
  END sum_i[468]
  PIN sum_i[469]
    DIRECTION INPUT ;
    USE SIGNAL ;
    PORT
      LAYER M5 ;
        RECT  138.432 68.952 138.456 69.144 ;
    END
  END sum_i[469]
  PIN sum_i[46]
    DIRECTION INPUT ;
    USE SIGNAL ;
    PORT
      LAYER M5 ;
        RECT  14.4 68.952 14.424 69.144 ;
    END
  END sum_i[46]
  PIN sum_i[470]
    DIRECTION INPUT ;
    USE SIGNAL ;
    PORT
      LAYER M5 ;
        RECT  138.528 68.952 138.552 69.144 ;
    END
  END sum_i[470]
  PIN sum_i[471]
    DIRECTION INPUT ;
    USE SIGNAL ;
    PORT
      LAYER M5 ;
        RECT  138.624 68.952 138.648 69.144 ;
    END
  END sum_i[471]
  PIN sum_i[472]
    DIRECTION INPUT ;
    USE SIGNAL ;
    PORT
      LAYER M5 ;
        RECT  138.72 68.952 138.744 69.144 ;
    END
  END sum_i[472]
  PIN sum_i[473]
    DIRECTION INPUT ;
    USE SIGNAL ;
    PORT
      LAYER M5 ;
        RECT  138.816 68.952 138.84 69.144 ;
    END
  END sum_i[473]
  PIN sum_i[474]
    DIRECTION INPUT ;
    USE SIGNAL ;
    PORT
      LAYER M5 ;
        RECT  138.912 68.952 138.936 69.144 ;
    END
  END sum_i[474]
  PIN sum_i[475]
    DIRECTION INPUT ;
    USE SIGNAL ;
    PORT
      LAYER M5 ;
        RECT  139.008 68.952 139.032 69.144 ;
    END
  END sum_i[475]
  PIN sum_i[476]
    DIRECTION INPUT ;
    USE SIGNAL ;
    PORT
      LAYER M5 ;
        RECT  139.104 68.952 139.128 69.144 ;
    END
  END sum_i[476]
  PIN sum_i[477]
    DIRECTION INPUT ;
    USE SIGNAL ;
    PORT
      LAYER M5 ;
        RECT  139.2 68.952 139.224 69.144 ;
    END
  END sum_i[477]
  PIN sum_i[478]
    DIRECTION INPUT ;
    USE SIGNAL ;
    PORT
      LAYER M5 ;
        RECT  139.296 68.952 139.32 69.144 ;
    END
  END sum_i[478]
  PIN sum_i[479]
    DIRECTION INPUT ;
    USE SIGNAL ;
    PORT
      LAYER M5 ;
        RECT  139.392 68.952 139.416 69.144 ;
    END
  END sum_i[479]
  PIN sum_i[47]
    DIRECTION INPUT ;
    USE SIGNAL ;
    PORT
      LAYER M5 ;
        RECT  14.496 68.952 14.52 69.144 ;
    END
  END sum_i[47]
  PIN sum_i[480]
    DIRECTION INPUT ;
    USE SIGNAL ;
    PORT
      LAYER M5 ;
        RECT  139.488 68.952 139.512 69.144 ;
    END
  END sum_i[480]
  PIN sum_i[481]
    DIRECTION INPUT ;
    USE SIGNAL ;
    PORT
      LAYER M5 ;
        RECT  139.584 68.952 139.608 69.144 ;
    END
  END sum_i[481]
  PIN sum_i[482]
    DIRECTION INPUT ;
    USE SIGNAL ;
    PORT
      LAYER M5 ;
        RECT  139.68 68.952 139.704 69.144 ;
    END
  END sum_i[482]
  PIN sum_i[483]
    DIRECTION INPUT ;
    USE SIGNAL ;
    PORT
      LAYER M5 ;
        RECT  139.776 68.952 139.8 69.144 ;
    END
  END sum_i[483]
  PIN sum_i[484]
    DIRECTION INPUT ;
    USE SIGNAL ;
    PORT
      LAYER M5 ;
        RECT  139.872 68.952 139.896 69.144 ;
    END
  END sum_i[484]
  PIN sum_i[485]
    DIRECTION INPUT ;
    USE SIGNAL ;
    PORT
      LAYER M5 ;
        RECT  139.968 68.952 139.992 69.144 ;
    END
  END sum_i[485]
  PIN sum_i[486]
    DIRECTION INPUT ;
    USE SIGNAL ;
    PORT
      LAYER M5 ;
        RECT  140.064 68.952 140.088 69.144 ;
    END
  END sum_i[486]
  PIN sum_i[487]
    DIRECTION INPUT ;
    USE SIGNAL ;
    PORT
      LAYER M5 ;
        RECT  140.16 68.952 140.184 69.144 ;
    END
  END sum_i[487]
  PIN sum_i[488]
    DIRECTION INPUT ;
    USE SIGNAL ;
    PORT
      LAYER M5 ;
        RECT  140.256 68.952 140.28 69.144 ;
    END
  END sum_i[488]
  PIN sum_i[489]
    DIRECTION INPUT ;
    USE SIGNAL ;
    PORT
      LAYER M5 ;
        RECT  140.352 68.952 140.376 69.144 ;
    END
  END sum_i[489]
  PIN sum_i[48]
    DIRECTION INPUT ;
    USE SIGNAL ;
    PORT
      LAYER M5 ;
        RECT  14.592 68.952 14.616 69.144 ;
    END
  END sum_i[48]
  PIN sum_i[490]
    DIRECTION INPUT ;
    USE SIGNAL ;
    PORT
      LAYER M5 ;
        RECT  140.448 68.952 140.472 69.144 ;
    END
  END sum_i[490]
  PIN sum_i[491]
    DIRECTION INPUT ;
    USE SIGNAL ;
    PORT
      LAYER M5 ;
        RECT  140.544 68.952 140.568 69.144 ;
    END
  END sum_i[491]
  PIN sum_i[492]
    DIRECTION INPUT ;
    USE SIGNAL ;
    PORT
      LAYER M5 ;
        RECT  140.64 68.952 140.664 69.144 ;
    END
  END sum_i[492]
  PIN sum_i[493]
    DIRECTION INPUT ;
    USE SIGNAL ;
    PORT
      LAYER M5 ;
        RECT  140.736 68.952 140.76 69.144 ;
    END
  END sum_i[493]
  PIN sum_i[494]
    DIRECTION INPUT ;
    USE SIGNAL ;
    PORT
      LAYER M5 ;
        RECT  140.832 68.952 140.856 69.144 ;
    END
  END sum_i[494]
  PIN sum_i[495]
    DIRECTION INPUT ;
    USE SIGNAL ;
    PORT
      LAYER M5 ;
        RECT  140.928 68.952 140.952 69.144 ;
    END
  END sum_i[495]
  PIN sum_i[496]
    DIRECTION INPUT ;
    USE SIGNAL ;
    PORT
      LAYER M5 ;
        RECT  141.024 68.952 141.048 69.144 ;
    END
  END sum_i[496]
  PIN sum_i[497]
    DIRECTION INPUT ;
    USE SIGNAL ;
    PORT
      LAYER M5 ;
        RECT  141.12 68.952 141.144 69.144 ;
    END
  END sum_i[497]
  PIN sum_i[498]
    DIRECTION INPUT ;
    USE SIGNAL ;
    PORT
      LAYER M5 ;
        RECT  141.216 68.952 141.24 69.144 ;
    END
  END sum_i[498]
  PIN sum_i[499]
    DIRECTION INPUT ;
    USE SIGNAL ;
    PORT
      LAYER M5 ;
        RECT  141.312 68.952 141.336 69.144 ;
    END
  END sum_i[499]
  PIN sum_i[49]
    DIRECTION INPUT ;
    USE SIGNAL ;
    PORT
      LAYER M5 ;
        RECT  14.688 68.952 14.712 69.144 ;
    END
  END sum_i[49]
  PIN sum_i[4]
    DIRECTION INPUT ;
    USE SIGNAL ;
    PORT
      LAYER M5 ;
        RECT  10.368 68.952 10.392 69.144 ;
    END
  END sum_i[4]
  PIN sum_i[500]
    DIRECTION INPUT ;
    USE SIGNAL ;
    PORT
      LAYER M5 ;
        RECT  141.408 68.952 141.432 69.144 ;
    END
  END sum_i[500]
  PIN sum_i[501]
    DIRECTION INPUT ;
    USE SIGNAL ;
    PORT
      LAYER M5 ;
        RECT  141.504 68.952 141.528 69.144 ;
    END
  END sum_i[501]
  PIN sum_i[502]
    DIRECTION INPUT ;
    USE SIGNAL ;
    PORT
      LAYER M5 ;
        RECT  141.6 68.952 141.624 69.144 ;
    END
  END sum_i[502]
  PIN sum_i[503]
    DIRECTION INPUT ;
    USE SIGNAL ;
    PORT
      LAYER M5 ;
        RECT  141.696 68.952 141.72 69.144 ;
    END
  END sum_i[503]
  PIN sum_i[504]
    DIRECTION INPUT ;
    USE SIGNAL ;
    PORT
      LAYER M5 ;
        RECT  141.792 68.952 141.816 69.144 ;
    END
  END sum_i[504]
  PIN sum_i[505]
    DIRECTION INPUT ;
    USE SIGNAL ;
    PORT
      LAYER M5 ;
        RECT  141.888 68.952 141.912 69.144 ;
    END
  END sum_i[505]
  PIN sum_i[506]
    DIRECTION INPUT ;
    USE SIGNAL ;
    PORT
      LAYER M5 ;
        RECT  141.984 68.952 142.008 69.144 ;
    END
  END sum_i[506]
  PIN sum_i[507]
    DIRECTION INPUT ;
    USE SIGNAL ;
    PORT
      LAYER M5 ;
        RECT  142.08 68.952 142.104 69.144 ;
    END
  END sum_i[507]
  PIN sum_i[508]
    DIRECTION INPUT ;
    USE SIGNAL ;
    PORT
      LAYER M5 ;
        RECT  142.176 68.952 142.2 69.144 ;
    END
  END sum_i[508]
  PIN sum_i[509]
    DIRECTION INPUT ;
    USE SIGNAL ;
    PORT
      LAYER M5 ;
        RECT  142.272 68.952 142.296 69.144 ;
    END
  END sum_i[509]
  PIN sum_i[50]
    DIRECTION INPUT ;
    USE SIGNAL ;
    PORT
      LAYER M5 ;
        RECT  14.784 68.952 14.808 69.144 ;
    END
  END sum_i[50]
  PIN sum_i[510]
    DIRECTION INPUT ;
    USE SIGNAL ;
    PORT
      LAYER M5 ;
        RECT  142.368 68.952 142.392 69.144 ;
    END
  END sum_i[510]
  PIN sum_i[511]
    DIRECTION INPUT ;
    USE SIGNAL ;
    PORT
      LAYER M5 ;
        RECT  142.464 68.952 142.488 69.144 ;
    END
  END sum_i[511]
  PIN sum_i[51]
    DIRECTION INPUT ;
    USE SIGNAL ;
    PORT
      LAYER M5 ;
        RECT  14.88 68.952 14.904 69.144 ;
    END
  END sum_i[51]
  PIN sum_i[52]
    DIRECTION INPUT ;
    USE SIGNAL ;
    PORT
      LAYER M5 ;
        RECT  14.976 68.952 15 69.144 ;
    END
  END sum_i[52]
  PIN sum_i[53]
    DIRECTION INPUT ;
    USE SIGNAL ;
    PORT
      LAYER M5 ;
        RECT  15.072 68.952 15.096 69.144 ;
    END
  END sum_i[53]
  PIN sum_i[54]
    DIRECTION INPUT ;
    USE SIGNAL ;
    PORT
      LAYER M5 ;
        RECT  15.168 68.952 15.192 69.144 ;
    END
  END sum_i[54]
  PIN sum_i[55]
    DIRECTION INPUT ;
    USE SIGNAL ;
    PORT
      LAYER M5 ;
        RECT  15.264 68.952 15.288 69.144 ;
    END
  END sum_i[55]
  PIN sum_i[56]
    DIRECTION INPUT ;
    USE SIGNAL ;
    PORT
      LAYER M5 ;
        RECT  15.36 68.952 15.384 69.144 ;
    END
  END sum_i[56]
  PIN sum_i[57]
    DIRECTION INPUT ;
    USE SIGNAL ;
    PORT
      LAYER M5 ;
        RECT  15.456 68.952 15.48 69.144 ;
    END
  END sum_i[57]
  PIN sum_i[58]
    DIRECTION INPUT ;
    USE SIGNAL ;
    PORT
      LAYER M5 ;
        RECT  15.552 68.952 15.576 69.144 ;
    END
  END sum_i[58]
  PIN sum_i[59]
    DIRECTION INPUT ;
    USE SIGNAL ;
    PORT
      LAYER M5 ;
        RECT  15.648 68.952 15.672 69.144 ;
    END
  END sum_i[59]
  PIN sum_i[5]
    DIRECTION INPUT ;
    USE SIGNAL ;
    PORT
      LAYER M5 ;
        RECT  10.464 68.952 10.488 69.144 ;
    END
  END sum_i[5]
  PIN sum_i[60]
    DIRECTION INPUT ;
    USE SIGNAL ;
    PORT
      LAYER M5 ;
        RECT  15.744 68.952 15.768 69.144 ;
    END
  END sum_i[60]
  PIN sum_i[61]
    DIRECTION INPUT ;
    USE SIGNAL ;
    PORT
      LAYER M5 ;
        RECT  15.84 68.952 15.864 69.144 ;
    END
  END sum_i[61]
  PIN sum_i[62]
    DIRECTION INPUT ;
    USE SIGNAL ;
    PORT
      LAYER M5 ;
        RECT  15.936 68.952 15.96 69.144 ;
    END
  END sum_i[62]
  PIN sum_i[63]
    DIRECTION INPUT ;
    USE SIGNAL ;
    PORT
      LAYER M5 ;
        RECT  16.032 68.952 16.056 69.144 ;
    END
  END sum_i[63]
  PIN sum_i[64]
    DIRECTION INPUT ;
    USE SIGNAL ;
    PORT
      LAYER M5 ;
        RECT  16.128 68.952 16.152 69.144 ;
    END
  END sum_i[64]
  PIN sum_i[65]
    DIRECTION INPUT ;
    USE SIGNAL ;
    PORT
      LAYER M5 ;
        RECT  16.224 68.952 16.248 69.144 ;
    END
  END sum_i[65]
  PIN sum_i[66]
    DIRECTION INPUT ;
    USE SIGNAL ;
    PORT
      LAYER M5 ;
        RECT  16.32 68.952 16.344 69.144 ;
    END
  END sum_i[66]
  PIN sum_i[67]
    DIRECTION INPUT ;
    USE SIGNAL ;
    PORT
      LAYER M5 ;
        RECT  16.416 68.952 16.44 69.144 ;
    END
  END sum_i[67]
  PIN sum_i[68]
    DIRECTION INPUT ;
    USE SIGNAL ;
    PORT
      LAYER M5 ;
        RECT  16.512 68.952 16.536 69.144 ;
    END
  END sum_i[68]
  PIN sum_i[69]
    DIRECTION INPUT ;
    USE SIGNAL ;
    PORT
      LAYER M5 ;
        RECT  16.608 68.952 16.632 69.144 ;
    END
  END sum_i[69]
  PIN sum_i[6]
    DIRECTION INPUT ;
    USE SIGNAL ;
    PORT
      LAYER M5 ;
        RECT  10.56 68.952 10.584 69.144 ;
    END
  END sum_i[6]
  PIN sum_i[70]
    DIRECTION INPUT ;
    USE SIGNAL ;
    PORT
      LAYER M5 ;
        RECT  16.704 68.952 16.728 69.144 ;
    END
  END sum_i[70]
  PIN sum_i[71]
    DIRECTION INPUT ;
    USE SIGNAL ;
    PORT
      LAYER M5 ;
        RECT  16.8 68.952 16.824 69.144 ;
    END
  END sum_i[71]
  PIN sum_i[72]
    DIRECTION INPUT ;
    USE SIGNAL ;
    PORT
      LAYER M5 ;
        RECT  16.896 68.952 16.92 69.144 ;
    END
  END sum_i[72]
  PIN sum_i[73]
    DIRECTION INPUT ;
    USE SIGNAL ;
    PORT
      LAYER M5 ;
        RECT  16.992 68.952 17.016 69.144 ;
    END
  END sum_i[73]
  PIN sum_i[74]
    DIRECTION INPUT ;
    USE SIGNAL ;
    PORT
      LAYER M5 ;
        RECT  17.088 68.952 17.112 69.144 ;
    END
  END sum_i[74]
  PIN sum_i[75]
    DIRECTION INPUT ;
    USE SIGNAL ;
    PORT
      LAYER M5 ;
        RECT  17.184 68.952 17.208 69.144 ;
    END
  END sum_i[75]
  PIN sum_i[76]
    DIRECTION INPUT ;
    USE SIGNAL ;
    PORT
      LAYER M5 ;
        RECT  17.28 68.952 17.304 69.144 ;
    END
  END sum_i[76]
  PIN sum_i[77]
    DIRECTION INPUT ;
    USE SIGNAL ;
    PORT
      LAYER M5 ;
        RECT  17.376 68.952 17.4 69.144 ;
    END
  END sum_i[77]
  PIN sum_i[78]
    DIRECTION INPUT ;
    USE SIGNAL ;
    PORT
      LAYER M5 ;
        RECT  17.472 68.952 17.496 69.144 ;
    END
  END sum_i[78]
  PIN sum_i[79]
    DIRECTION INPUT ;
    USE SIGNAL ;
    PORT
      LAYER M5 ;
        RECT  17.568 68.952 17.592 69.144 ;
    END
  END sum_i[79]
  PIN sum_i[7]
    DIRECTION INPUT ;
    USE SIGNAL ;
    PORT
      LAYER M5 ;
        RECT  10.656 68.952 10.68 69.144 ;
    END
  END sum_i[7]
  PIN sum_i[80]
    DIRECTION INPUT ;
    USE SIGNAL ;
    PORT
      LAYER M5 ;
        RECT  17.664 68.952 17.688 69.144 ;
    END
  END sum_i[80]
  PIN sum_i[81]
    DIRECTION INPUT ;
    USE SIGNAL ;
    PORT
      LAYER M5 ;
        RECT  17.76 68.952 17.784 69.144 ;
    END
  END sum_i[81]
  PIN sum_i[82]
    DIRECTION INPUT ;
    USE SIGNAL ;
    PORT
      LAYER M5 ;
        RECT  17.856 68.952 17.88 69.144 ;
    END
  END sum_i[82]
  PIN sum_i[83]
    DIRECTION INPUT ;
    USE SIGNAL ;
    PORT
      LAYER M5 ;
        RECT  17.952 68.952 17.976 69.144 ;
    END
  END sum_i[83]
  PIN sum_i[84]
    DIRECTION INPUT ;
    USE SIGNAL ;
    PORT
      LAYER M5 ;
        RECT  18.048 68.952 18.072 69.144 ;
    END
  END sum_i[84]
  PIN sum_i[85]
    DIRECTION INPUT ;
    USE SIGNAL ;
    PORT
      LAYER M5 ;
        RECT  18.144 68.952 18.168 69.144 ;
    END
  END sum_i[85]
  PIN sum_i[86]
    DIRECTION INPUT ;
    USE SIGNAL ;
    PORT
      LAYER M5 ;
        RECT  18.24 68.952 18.264 69.144 ;
    END
  END sum_i[86]
  PIN sum_i[87]
    DIRECTION INPUT ;
    USE SIGNAL ;
    PORT
      LAYER M5 ;
        RECT  18.336 68.952 18.36 69.144 ;
    END
  END sum_i[87]
  PIN sum_i[88]
    DIRECTION INPUT ;
    USE SIGNAL ;
    PORT
      LAYER M5 ;
        RECT  18.432 68.952 18.456 69.144 ;
    END
  END sum_i[88]
  PIN sum_i[89]
    DIRECTION INPUT ;
    USE SIGNAL ;
    PORT
      LAYER M5 ;
        RECT  18.528 68.952 18.552 69.144 ;
    END
  END sum_i[89]
  PIN sum_i[8]
    DIRECTION INPUT ;
    USE SIGNAL ;
    PORT
      LAYER M5 ;
        RECT  10.752 68.952 10.776 69.144 ;
    END
  END sum_i[8]
  PIN sum_i[90]
    DIRECTION INPUT ;
    USE SIGNAL ;
    PORT
      LAYER M5 ;
        RECT  18.624 68.952 18.648 69.144 ;
    END
  END sum_i[90]
  PIN sum_i[91]
    DIRECTION INPUT ;
    USE SIGNAL ;
    PORT
      LAYER M5 ;
        RECT  18.72 68.952 18.744 69.144 ;
    END
  END sum_i[91]
  PIN sum_i[92]
    DIRECTION INPUT ;
    USE SIGNAL ;
    PORT
      LAYER M5 ;
        RECT  18.816 68.952 18.84 69.144 ;
    END
  END sum_i[92]
  PIN sum_i[93]
    DIRECTION INPUT ;
    USE SIGNAL ;
    PORT
      LAYER M5 ;
        RECT  18.912 68.952 18.936 69.144 ;
    END
  END sum_i[93]
  PIN sum_i[94]
    DIRECTION INPUT ;
    USE SIGNAL ;
    PORT
      LAYER M5 ;
        RECT  19.008 68.952 19.032 69.144 ;
    END
  END sum_i[94]
  PIN sum_i[95]
    DIRECTION INPUT ;
    USE SIGNAL ;
    PORT
      LAYER M5 ;
        RECT  19.104 68.952 19.128 69.144 ;
    END
  END sum_i[95]
  PIN sum_i[96]
    DIRECTION INPUT ;
    USE SIGNAL ;
    PORT
      LAYER M5 ;
        RECT  19.2 68.952 19.224 69.144 ;
    END
  END sum_i[96]
  PIN sum_i[97]
    DIRECTION INPUT ;
    USE SIGNAL ;
    PORT
      LAYER M5 ;
        RECT  19.296 68.952 19.32 69.144 ;
    END
  END sum_i[97]
  PIN sum_i[98]
    DIRECTION INPUT ;
    USE SIGNAL ;
    PORT
      LAYER M5 ;
        RECT  19.392 68.952 19.416 69.144 ;
    END
  END sum_i[98]
  PIN sum_i[99]
    DIRECTION INPUT ;
    USE SIGNAL ;
    PORT
      LAYER M5 ;
        RECT  19.488 68.952 19.512 69.144 ;
    END
  END sum_i[99]
  PIN sum_i[9]
    DIRECTION INPUT ;
    USE SIGNAL ;
    PORT
      LAYER M5 ;
        RECT  10.848 68.952 10.872 69.144 ;
    END
  END sum_i[9]
  PIN y[0]
    DIRECTION OUTPUT ;
    USE SIGNAL ;
    PORT
      LAYER M4 ;
        RECT  194.208 30.144 194.4 30.168 ;
    END
  END y[0]
  PIN y[10]
    DIRECTION OUTPUT ;
    USE SIGNAL ;
    PORT
      LAYER M4 ;
        RECT  194.208 32.064 194.4 32.088 ;
    END
  END y[10]
  PIN y[11]
    DIRECTION OUTPUT ;
    USE SIGNAL ;
    PORT
      LAYER M4 ;
        RECT  194.208 32.256 194.4 32.28 ;
    END
  END y[11]
  PIN y[12]
    DIRECTION OUTPUT ;
    USE SIGNAL ;
    PORT
      LAYER M4 ;
        RECT  194.208 32.448 194.4 32.472 ;
    END
  END y[12]
  PIN y[13]
    DIRECTION OUTPUT ;
    USE SIGNAL ;
    PORT
      LAYER M4 ;
        RECT  194.208 32.64 194.4 32.664 ;
    END
  END y[13]
  PIN y[14]
    DIRECTION OUTPUT ;
    USE SIGNAL ;
    PORT
      LAYER M4 ;
        RECT  194.208 32.832 194.4 32.856 ;
    END
  END y[14]
  PIN y[15]
    DIRECTION OUTPUT ;
    USE SIGNAL ;
    PORT
      LAYER M4 ;
        RECT  194.208 33.024 194.4 33.048 ;
    END
  END y[15]
  PIN y[16]
    DIRECTION OUTPUT ;
    USE SIGNAL ;
    PORT
      LAYER M4 ;
        RECT  194.208 33.216 194.4 33.24 ;
    END
  END y[16]
  PIN y[17]
    DIRECTION OUTPUT ;
    USE SIGNAL ;
    PORT
      LAYER M4 ;
        RECT  194.208 33.408 194.4 33.432 ;
    END
  END y[17]
  PIN y[18]
    DIRECTION OUTPUT ;
    USE SIGNAL ;
    PORT
      LAYER M4 ;
        RECT  194.208 33.6 194.4 33.624 ;
    END
  END y[18]
  PIN y[19]
    DIRECTION OUTPUT ;
    USE SIGNAL ;
    PORT
      LAYER M4 ;
        RECT  194.208 33.792 194.4 33.816 ;
    END
  END y[19]
  PIN y[1]
    DIRECTION OUTPUT ;
    USE SIGNAL ;
    PORT
      LAYER M4 ;
        RECT  194.208 30.336 194.4 30.36 ;
    END
  END y[1]
  PIN y[20]
    DIRECTION OUTPUT ;
    USE SIGNAL ;
    PORT
      LAYER M4 ;
        RECT  194.208 33.984 194.4 34.008 ;
    END
  END y[20]
  PIN y[21]
    DIRECTION OUTPUT ;
    USE SIGNAL ;
    PORT
      LAYER M4 ;
        RECT  194.208 34.176 194.4 34.2 ;
    END
  END y[21]
  PIN y[22]
    DIRECTION OUTPUT ;
    USE SIGNAL ;
    PORT
      LAYER M4 ;
        RECT  194.208 34.368 194.4 34.392 ;
    END
  END y[22]
  PIN y[23]
    DIRECTION OUTPUT ;
    USE SIGNAL ;
    PORT
      LAYER M4 ;
        RECT  194.208 34.56 194.4 34.584 ;
    END
  END y[23]
  PIN y[24]
    DIRECTION OUTPUT ;
    USE SIGNAL ;
    PORT
      LAYER M4 ;
        RECT  194.208 34.752 194.4 34.776 ;
    END
  END y[24]
  PIN y[25]
    DIRECTION OUTPUT ;
    USE SIGNAL ;
    PORT
      LAYER M4 ;
        RECT  194.208 34.944 194.4 34.968 ;
    END
  END y[25]
  PIN y[26]
    DIRECTION OUTPUT ;
    USE SIGNAL ;
    PORT
      LAYER M4 ;
        RECT  194.208 35.136 194.4 35.16 ;
    END
  END y[26]
  PIN y[27]
    DIRECTION OUTPUT ;
    USE SIGNAL ;
    PORT
      LAYER M4 ;
        RECT  194.208 35.328 194.4 35.352 ;
    END
  END y[27]
  PIN y[28]
    DIRECTION OUTPUT ;
    USE SIGNAL ;
    PORT
      LAYER M4 ;
        RECT  194.208 35.52 194.4 35.544 ;
    END
  END y[28]
  PIN y[29]
    DIRECTION OUTPUT ;
    USE SIGNAL ;
    PORT
      LAYER M4 ;
        RECT  194.208 35.712 194.4 35.736 ;
    END
  END y[29]
  PIN y[2]
    DIRECTION OUTPUT ;
    USE SIGNAL ;
    PORT
      LAYER M4 ;
        RECT  194.208 30.528 194.4 30.552 ;
    END
  END y[2]
  PIN y[30]
    DIRECTION OUTPUT ;
    USE SIGNAL ;
    PORT
      LAYER M4 ;
        RECT  194.208 35.904 194.4 35.928 ;
    END
  END y[30]
  PIN y[31]
    DIRECTION OUTPUT ;
    USE SIGNAL ;
    PORT
      LAYER M4 ;
        RECT  194.208 36.096 194.4 36.12 ;
    END
  END y[31]
  PIN y[3]
    DIRECTION OUTPUT ;
    USE SIGNAL ;
    PORT
      LAYER M4 ;
        RECT  194.208 30.72 194.4 30.744 ;
    END
  END y[3]
  PIN y[4]
    DIRECTION OUTPUT ;
    USE SIGNAL ;
    PORT
      LAYER M4 ;
        RECT  194.208 30.912 194.4 30.936 ;
    END
  END y[4]
  PIN y[5]
    DIRECTION OUTPUT ;
    USE SIGNAL ;
    PORT
      LAYER M4 ;
        RECT  194.208 31.104 194.4 31.128 ;
    END
  END y[5]
  PIN y[6]
    DIRECTION OUTPUT ;
    USE SIGNAL ;
    PORT
      LAYER M4 ;
        RECT  194.208 31.296 194.4 31.32 ;
    END
  END y[6]
  PIN y[7]
    DIRECTION OUTPUT ;
    USE SIGNAL ;
    PORT
      LAYER M4 ;
        RECT  194.208 31.488 194.4 31.512 ;
    END
  END y[7]
  PIN y[8]
    DIRECTION OUTPUT ;
    USE SIGNAL ;
    PORT
      LAYER M4 ;
        RECT  194.208 31.68 194.4 31.704 ;
    END
  END y[8]
  PIN y[9]
    DIRECTION OUTPUT ;
    USE SIGNAL ;
    PORT
      LAYER M4 ;
        RECT  194.208 31.872 194.4 31.896 ;
    END
  END y[9]
  PIN VDD
    DIRECTION INOUT ;
    USE POWER ;
    PORT
      LAYER M6 ;
        RECT  0.468 57.32 193.932 57.608 ;
        RECT  0.468 46.52 193.932 46.808 ;
        RECT  0.468 35.72 193.932 36.008 ;
        RECT  0.468 24.92 193.932 25.208 ;
        RECT  0.468 14.12 193.932 14.408 ;
        RECT  0.468 3.32 193.932 3.608 ;
        RECT  0.468 68.724 193.932 69.012 ;
        RECT  0.468 0.108 193.932 0.396 ;
    END
  END VDD
  PIN VSS
    DIRECTION INOUT ;
    USE GROUND ;
    PORT
      LAYER M6 ;
        RECT  0.468 67.736 193.932 68.024 ;
        RECT  0.468 56.936 193.932 57.224 ;
        RECT  0.468 46.136 193.932 46.424 ;
        RECT  0.468 35.336 193.932 35.624 ;
        RECT  0.468 24.536 193.932 24.824 ;
        RECT  0.468 13.736 193.932 14.024 ;
        RECT  0.468 2.936 193.932 3.224 ;
        RECT  0.66 68.34 193.74 68.628 ;
        RECT  0.66 0.492 193.74 0.78 ;
    END
  END VSS
  OBS
    LAYER RVTN ;
     RECT  0 0 194.4 69.144 ;
    LAYER RVTP ;
     RECT  0 0 194.4 69.144 ;
    LAYER M1 ;
     RECT  0 0 194.4 69.144 ;
    LAYER M2 ;
     RECT  0 0 194.4 69.144 ;
    LAYER M3 ;
     RECT  0 0 194.4 69.144 ;
    LAYER M4 ;
     RECT  0 0 194.4 69.144 ;
    LAYER M5 ;
     RECT  0 0 194.4 69.144 ;
    LAYER M6 ;
     RECT  0 0 194.4 69.144 ;
  END
END ot_hbm_accel_smh_tct
END LIBRARY
